// Mitsubishi GX Works2 project: BACK PANEL(TakeOff)(230727)   PLC: Q06UDV

PROGRAM MAIN
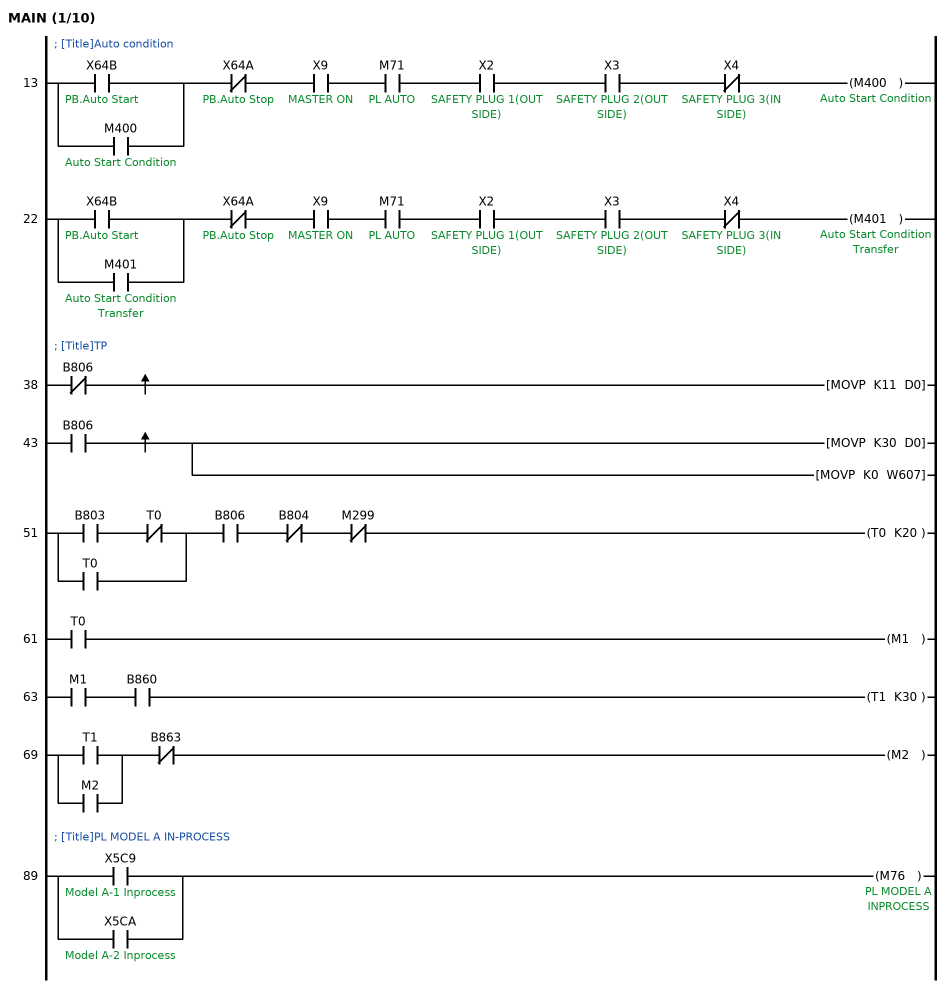
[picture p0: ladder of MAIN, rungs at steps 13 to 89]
; [Title]Auto condition
13    LD      X64B  ; PB.Auto Start
      OR      M400  ; Auto Start Condition
      ANI     X64A  ; PB.Auto Stop
      AND     X9  ; MASTER ON
      AND     M71  ; PL AUTO
      AND     X2  ; SAFETY PLUG 1(OUT SIDE)
      AND     X3  ; SAFETY PLUG 2(OUT SIDE)
      ANI     X4  ; SAFETY PLUG 3(IN SIDE)
      OUT     M400  ; Auto Start Condition
22    LD      X64B  ; PB.Auto Start
      OR      M401  ; Auto Start Condition Transfer
      ANI     X64A  ; PB.Auto Stop
      AND     X9  ; MASTER ON
      AND     M71  ; PL AUTO
      AND     X2  ; SAFETY PLUG 1(OUT SIDE)
      AND     X3  ; SAFETY PLUG 2(OUT SIDE)
      ANI     X4  ; SAFETY PLUG 3(IN SIDE)
      OUT     M401  ; Auto Start Condition Transfer
; [Title]TP
38    LDI     B806
      MEP
      MOVP    K11 D0
43    LD      B806
      MEP
      MOVP    K30 D0
      MOVP    K0 W607
51    LD      B803
      ANI     T0
      OR      T0
      AND     B806
      ANI     B804
      ANI     M299
      OUT     T0 K20
61    LD      T0
      OUT     M1
63    LD      M1
      AND     B860
      OUT     T1 K30
69    LD      T1
      OR      M2
      ANI     B863
      OUT     M2
; [Title]PL MODEL A IN-PROCESS
89    LD      X5C9  ; Model A-1 Inprocess
      OR      X5CA  ; Model A-2 Inprocess
      OUT     M76  ; PL MODEL A INPROCESS
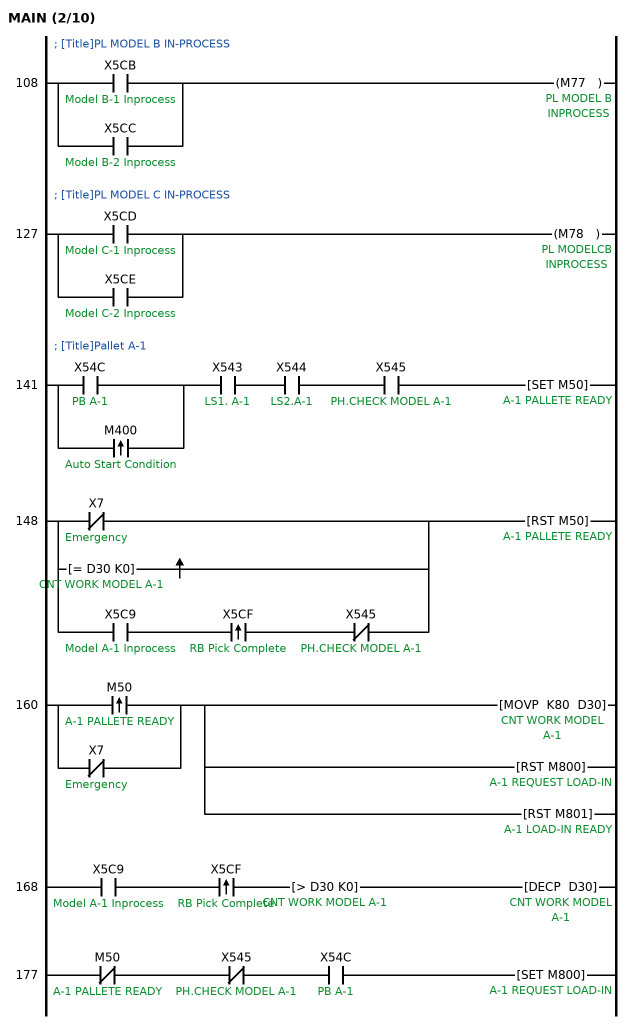
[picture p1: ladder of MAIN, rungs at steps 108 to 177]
; [Title]PL MODEL B IN-PROCESS
108   LD      X5CB  ; Model B-1 Inprocess
      OR      X5CC  ; Model B-2 Inprocess
      OUT     M77  ; PL MODEL B INPROCESS
; [Title]PL MODEL C IN-PROCESS
127   LD      X5CD  ; Model C-1 Inprocess
      OR      X5CE  ; Model C-2 Inprocess
      OUT     M78  ; PL MODELCB INPROCESS
; [Title]Pallet A-1
141   LD      X54C  ; PB A-1
      ORP     M400  ; Auto Start Condition
      AND     X543  ; LS1. A-1
      AND     X544  ; LS2.A-1
      AND     X545  ; PH.CHECK MODEL A-1
      SET     M50  ; A-1 PALLETE READY
148   LDI     X7  ; Emergency
      LD=     D30 K0  ; CNT WORK MODEL A-1
      MEP
      ORB
      LD      X5C9  ; Model A-1 Inprocess
      ANDP    X5CF  ; RB Pick Complete
      ANI     X545  ; PH.CHECK MODEL A-1
      ORB
      RST     M50  ; A-1 PALLETE READY
160   LDP     M50  ; A-1 PALLETE READY
      ORI     X7  ; Emergency
      MOVP    K80 D30
      RST     M800  ; A-1 REQUEST LOAD-IN
      RST     M801  ; A-1 LOAD-IN READY
168   LD      X5C9  ; Model A-1 Inprocess
      ANDP    X5CF  ; RB Pick Complete
      AND>    D30 K0  ; CNT WORK MODEL A-1
      DECP    D30
177   LDI     M50  ; A-1 PALLETE READY
      ANI     X545  ; PH.CHECK MODEL A-1
      AND     X54C  ; PB A-1
      SET     M800  ; A-1 REQUEST LOAD-IN
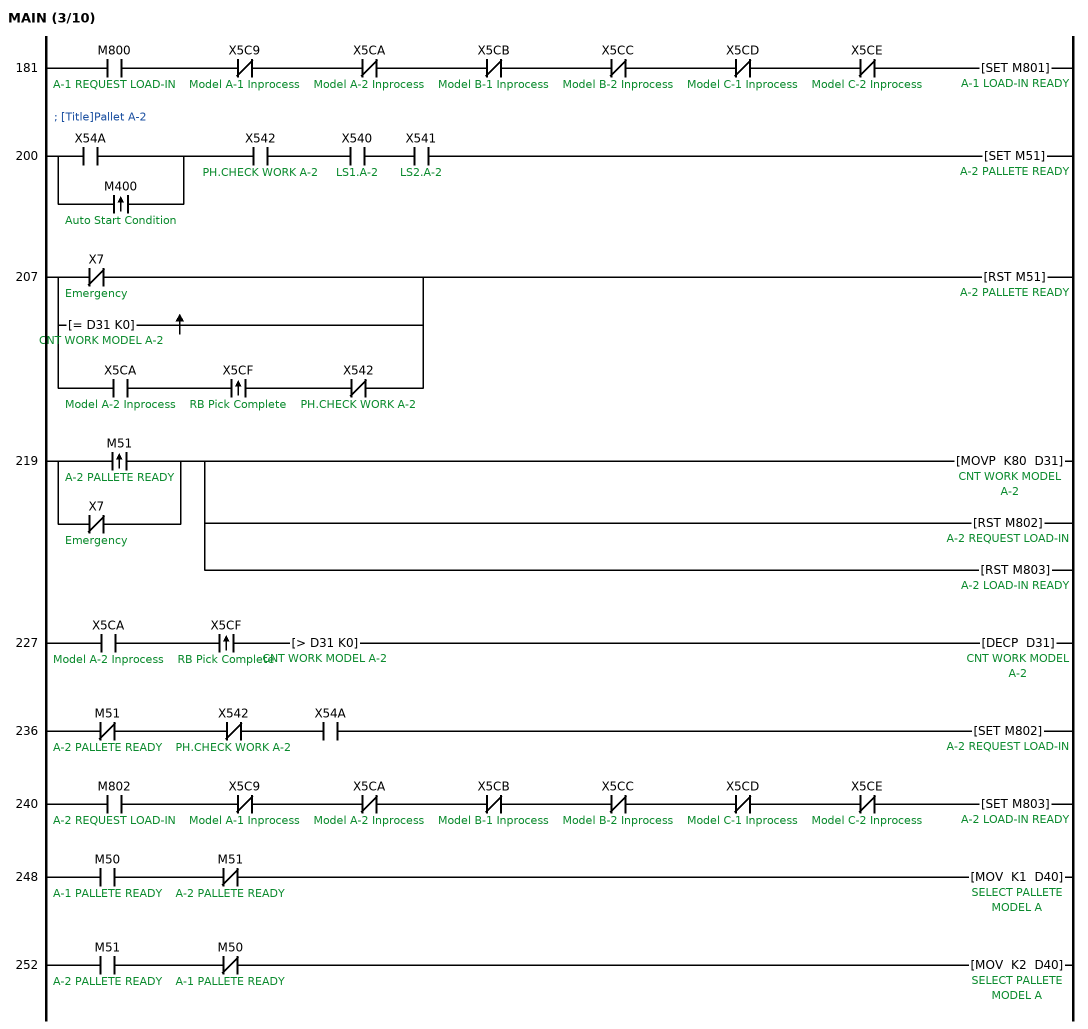
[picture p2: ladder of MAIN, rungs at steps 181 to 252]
181   LD      M800  ; A-1 REQUEST LOAD-IN
      ANI     X5C9  ; Model A-1 Inprocess
      ANI     X5CA  ; Model A-2 Inprocess
      ANI     X5CB  ; Model B-1 Inprocess
      ANI     X5CC  ; Model B-2 Inprocess
      ANI     X5CD  ; Model C-1 Inprocess
      ANI     X5CE  ; Model C-2 Inprocess
      SET     M801  ; A-1 LOAD-IN READY
; [Title]Pallet A-2
200   LD      X54A
      ORP     M400  ; Auto Start Condition
      AND     X542  ; PH.CHECK WORK A-2
      AND     X540  ; LS1.A-2
      AND     X541  ; LS2.A-2
      SET     M51  ; A-2 PALLETE READY
207   LDI     X7  ; Emergency
      LD=     D31 K0  ; CNT WORK MODEL A-2
      MEP
      ORB
      LD      X5CA  ; Model A-2 Inprocess
      ANDP    X5CF  ; RB Pick Complete
      ANI     X542  ; PH.CHECK WORK A-2
      ORB
      RST     M51  ; A-2 PALLETE READY
219   LDP     M51  ; A-2 PALLETE READY
      ORI     X7  ; Emergency
      MOVP    K80 D31
      RST     M802  ; A-2 REQUEST LOAD-IN
      RST     M803  ; A-2 LOAD-IN READY
227   LD      X5CA  ; Model A-2 Inprocess
      ANDP    X5CF  ; RB Pick Complete
      AND>    D31 K0  ; CNT WORK MODEL A-2
      DECP    D31
236   LDI     M51  ; A-2 PALLETE READY
      ANI     X542  ; PH.CHECK WORK A-2
      AND     X54A
      SET     M802  ; A-2 REQUEST LOAD-IN
240   LD      M802  ; A-2 REQUEST LOAD-IN
      ANI     X5C9  ; Model A-1 Inprocess
      ANI     X5CA  ; Model A-2 Inprocess
      ANI     X5CB  ; Model B-1 Inprocess
      ANI     X5CC  ; Model B-2 Inprocess
      ANI     X5CD  ; Model C-1 Inprocess
      ANI     X5CE  ; Model C-2 Inprocess
      SET     M803  ; A-2 LOAD-IN READY
248   LD      M50  ; A-1 PALLETE READY
      ANI     M51  ; A-2 PALLETE READY
      MOV     K1 D40  ; SELECT PALLETE MODEL A
252   LD      M51  ; A-2 PALLETE READY
      ANI     M50  ; A-1 PALLETE READY
      MOV     K2 D40
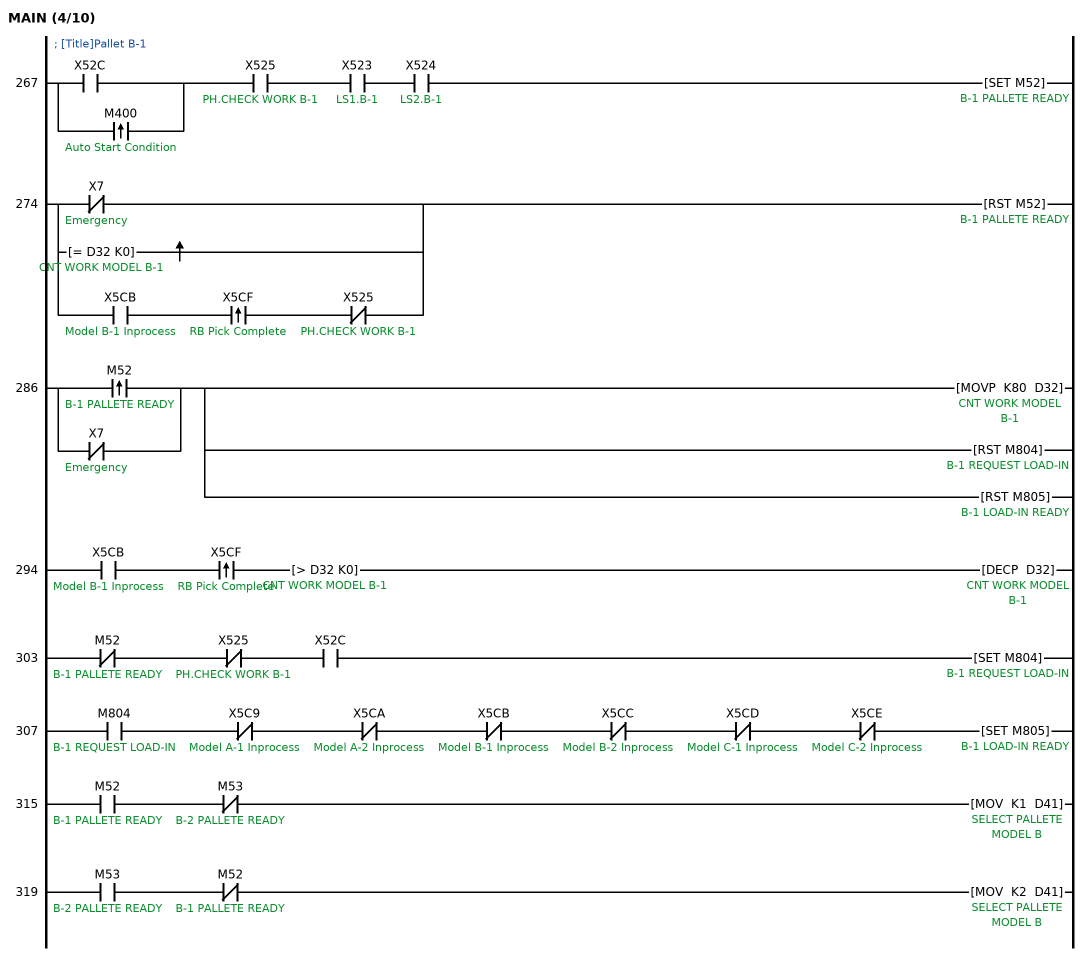
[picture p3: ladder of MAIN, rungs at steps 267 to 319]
; [Title]Pallet B-1
267   LD      X52C
      ORP     M400  ; Auto Start Condition
      AND     X525  ; PH.CHECK WORK B-1
      AND     X523  ; LS1.B-1
      AND     X524  ; LS2.B-1
      SET     M52  ; B-1 PALLETE READY
274   LDI     X7  ; Emergency
      LD=     D32 K0  ; CNT WORK MODEL B-1
      MEP
      ORB
      LD      X5CB  ; Model B-1 Inprocess
      ANDP    X5CF  ; RB Pick Complete
      ANI     X525  ; PH.CHECK WORK B-1
      ORB
      RST     M52  ; B-1 PALLETE READY
286   LDP     M52  ; B-1 PALLETE READY
      ORI     X7  ; Emergency
      MOVP    K80 D32
      RST     M804  ; B-1 REQUEST LOAD-IN
      RST     M805  ; B-1 LOAD-IN READY
294   LD      X5CB  ; Model B-1 Inprocess
      ANDP    X5CF  ; RB Pick Complete
      AND>    D32 K0  ; CNT WORK MODEL B-1
      DECP    D32
303   LDI     M52  ; B-1 PALLETE READY
      ANI     X525  ; PH.CHECK WORK B-1
      AND     X52C
      SET     M804  ; B-1 REQUEST LOAD-IN
307   LD      M804  ; B-1 REQUEST LOAD-IN
      ANI     X5C9  ; Model A-1 Inprocess
      ANI     X5CA  ; Model A-2 Inprocess
      ANI     X5CB  ; Model B-1 Inprocess
      ANI     X5CC  ; Model B-2 Inprocess
      ANI     X5CD  ; Model C-1 Inprocess
      ANI     X5CE  ; Model C-2 Inprocess
      SET     M805  ; B-1 LOAD-IN READY
315   LD      M52  ; B-1 PALLETE READY
      ANI     M53  ; B-2 PALLETE READY
      MOV     K1 D41  ; SELECT PALLETE MODEL B
319   LD      M53  ; B-2 PALLETE READY
      ANI     M52  ; B-1 PALLETE READY
      MOV     K2 D41
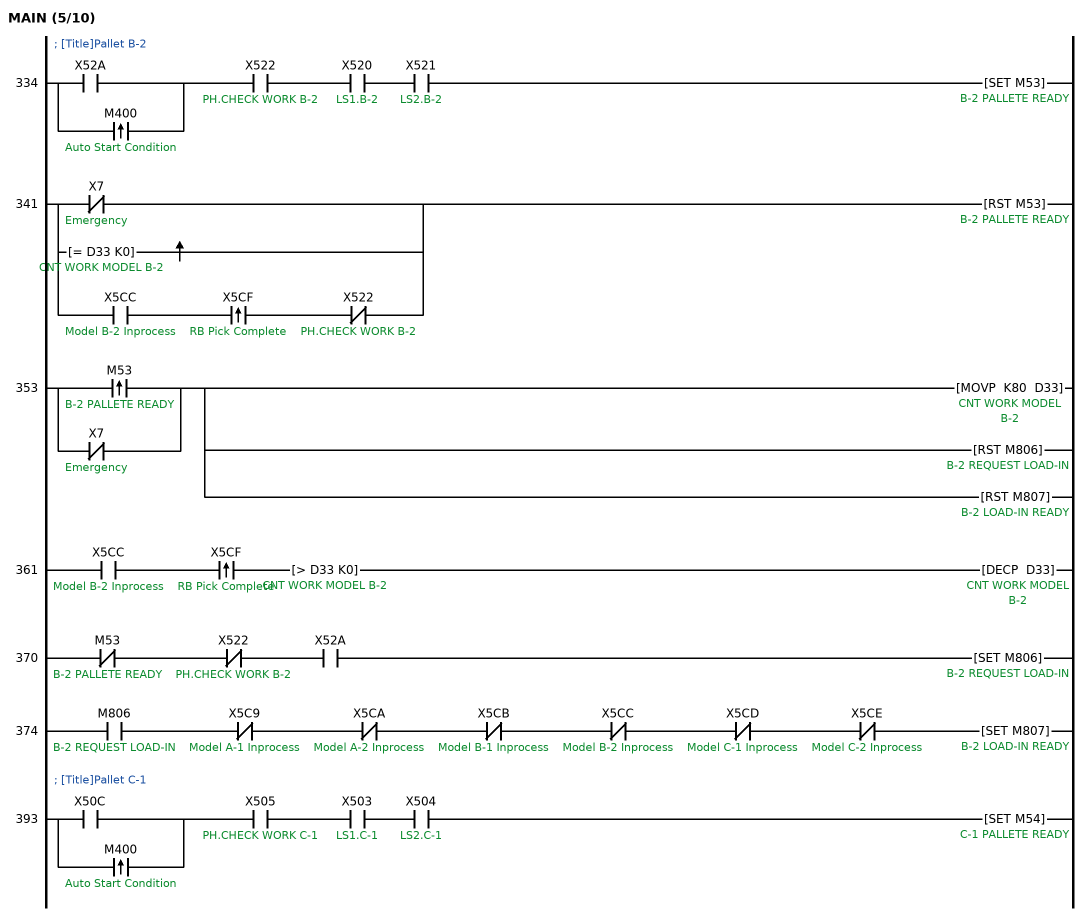
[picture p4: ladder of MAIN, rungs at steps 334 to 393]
; [Title]Pallet B-2
334   LD      X52A
      ORP     M400  ; Auto Start Condition
      AND     X522  ; PH.CHECK WORK B-2
      AND     X520  ; LS1.B-2
      AND     X521  ; LS2.B-2
      SET     M53  ; B-2 PALLETE READY
341   LDI     X7  ; Emergency
      LD=     D33 K0  ; CNT WORK MODEL B-2
      MEP
      ORB
      LD      X5CC  ; Model B-2 Inprocess
      ANDP    X5CF  ; RB Pick Complete
      ANI     X522  ; PH.CHECK WORK B-2
      ORB
      RST     M53  ; B-2 PALLETE READY
353   LDP     M53  ; B-2 PALLETE READY
      ORI     X7  ; Emergency
      MOVP    K80 D33
      RST     M806  ; B-2 REQUEST LOAD-IN
      RST     M807  ; B-2 LOAD-IN READY
361   LD      X5CC  ; Model B-2 Inprocess
      ANDP    X5CF  ; RB Pick Complete
      AND>    D33 K0  ; CNT WORK MODEL B-2
      DECP    D33
370   LDI     M53  ; B-2 PALLETE READY
      ANI     X522  ; PH.CHECK WORK B-2
      AND     X52A
      SET     M806  ; B-2 REQUEST LOAD-IN
374   LD      M806  ; B-2 REQUEST LOAD-IN
      ANI     X5C9  ; Model A-1 Inprocess
      ANI     X5CA  ; Model A-2 Inprocess
      ANI     X5CB  ; Model B-1 Inprocess
      ANI     X5CC  ; Model B-2 Inprocess
      ANI     X5CD  ; Model C-1 Inprocess
      ANI     X5CE  ; Model C-2 Inprocess
      SET     M807  ; B-2 LOAD-IN READY
; [Title]Pallet C-1
393   LD      X50C
      ORP     M400  ; Auto Start Condition
      AND     X505  ; PH.CHECK WORK C-1
      AND     X503  ; LS1.C-1
      AND     X504  ; LS2.C-1
      SET     M54  ; C-1 PALLETE READY
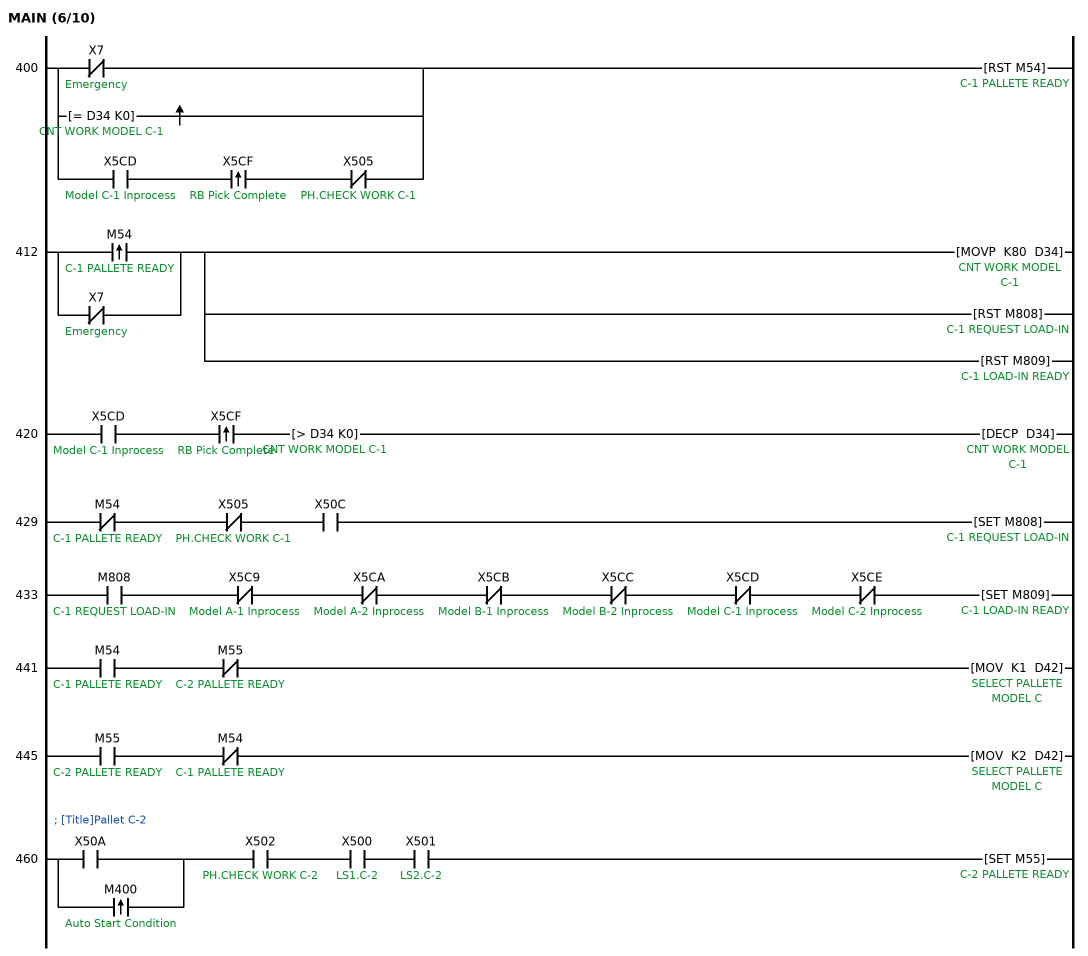
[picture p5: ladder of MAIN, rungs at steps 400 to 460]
400   LDI     X7  ; Emergency
      LD=     D34 K0  ; CNT WORK MODEL C-1
      MEP
      ORB
      LD      X5CD  ; Model C-1 Inprocess
      ANDP    X5CF  ; RB Pick Complete
      ANI     X505  ; PH.CHECK WORK C-1
      ORB
      RST     M54  ; C-1 PALLETE READY
412   LDP     M54  ; C-1 PALLETE READY
      ORI     X7  ; Emergency
      MOVP    K80 D34
      RST     M808  ; C-1 REQUEST LOAD-IN
      RST     M809  ; C-1 LOAD-IN READY
420   LD      X5CD  ; Model C-1 Inprocess
      ANDP    X5CF  ; RB Pick Complete
      AND>    D34 K0  ; CNT WORK MODEL C-1
      DECP    D34
429   LDI     M54  ; C-1 PALLETE READY
      ANI     X505  ; PH.CHECK WORK C-1
      AND     X50C
      SET     M808  ; C-1 REQUEST LOAD-IN
433   LD      M808  ; C-1 REQUEST LOAD-IN
      ANI     X5C9  ; Model A-1 Inprocess
      ANI     X5CA  ; Model A-2 Inprocess
      ANI     X5CB  ; Model B-1 Inprocess
      ANI     X5CC  ; Model B-2 Inprocess
      ANI     X5CD  ; Model C-1 Inprocess
      ANI     X5CE  ; Model C-2 Inprocess
      SET     M809  ; C-1 LOAD-IN READY
441   LD      M54  ; C-1 PALLETE READY
      ANI     M55  ; C-2 PALLETE READY
      MOV     K1 D42  ; SELECT PALLETE MODEL C
445   LD      M55  ; C-2 PALLETE READY
      ANI     M54  ; C-1 PALLETE READY
      MOV     K2 D42
; [Title]Pallet C-2
460   LD      X50A
      ORP     M400  ; Auto Start Condition
      AND     X502  ; PH.CHECK WORK C-2
      AND     X500  ; LS1.C-2
      AND     X501  ; LS2.C-2
      SET     M55  ; C-2 PALLETE READY
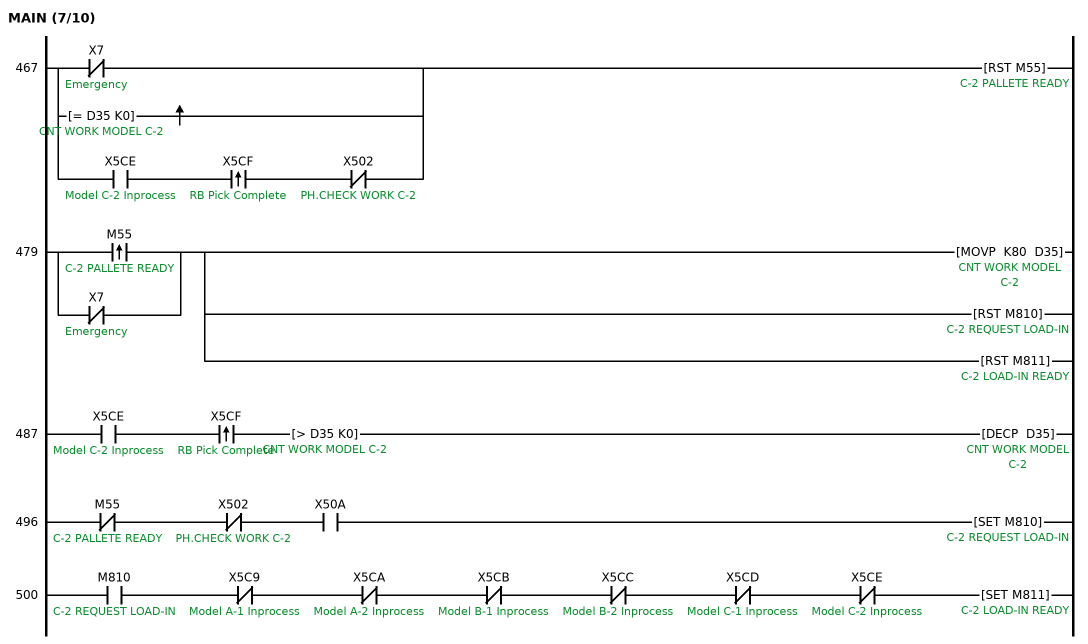
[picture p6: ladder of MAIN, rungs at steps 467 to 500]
467   LDI     X7  ; Emergency
      LD=     D35 K0  ; CNT WORK MODEL C-2
      MEP
      ORB
      LD      X5CE  ; Model C-2 Inprocess
      ANDP    X5CF  ; RB Pick Complete
      ANI     X502  ; PH.CHECK WORK C-2
      ORB
      RST     M55  ; C-2 PALLETE READY
479   LDP     M55  ; C-2 PALLETE READY
      ORI     X7  ; Emergency
      MOVP    K80 D35
      RST     M810  ; C-2 REQUEST LOAD-IN
      RST     M811  ; C-2 LOAD-IN READY
487   LD      X5CE  ; Model C-2 Inprocess
      ANDP    X5CF  ; RB Pick Complete
      AND>    D35 K0  ; CNT WORK MODEL C-2
      DECP    D35
496   LDI     M55  ; C-2 PALLETE READY
      ANI     X502  ; PH.CHECK WORK C-2
      AND     X50A
      SET     M810  ; C-2 REQUEST LOAD-IN
500   LD      M810  ; C-2 REQUEST LOAD-IN
      ANI     X5C9  ; Model A-1 Inprocess
      ANI     X5CA  ; Model A-2 Inprocess
      ANI     X5CB  ; Model B-1 Inprocess
      ANI     X5CC  ; Model B-2 Inprocess
      ANI     X5CD  ; Model C-1 Inprocess
      ANI     X5CE  ; Model C-2 Inprocess
      SET     M811  ; C-2 LOAD-IN READY
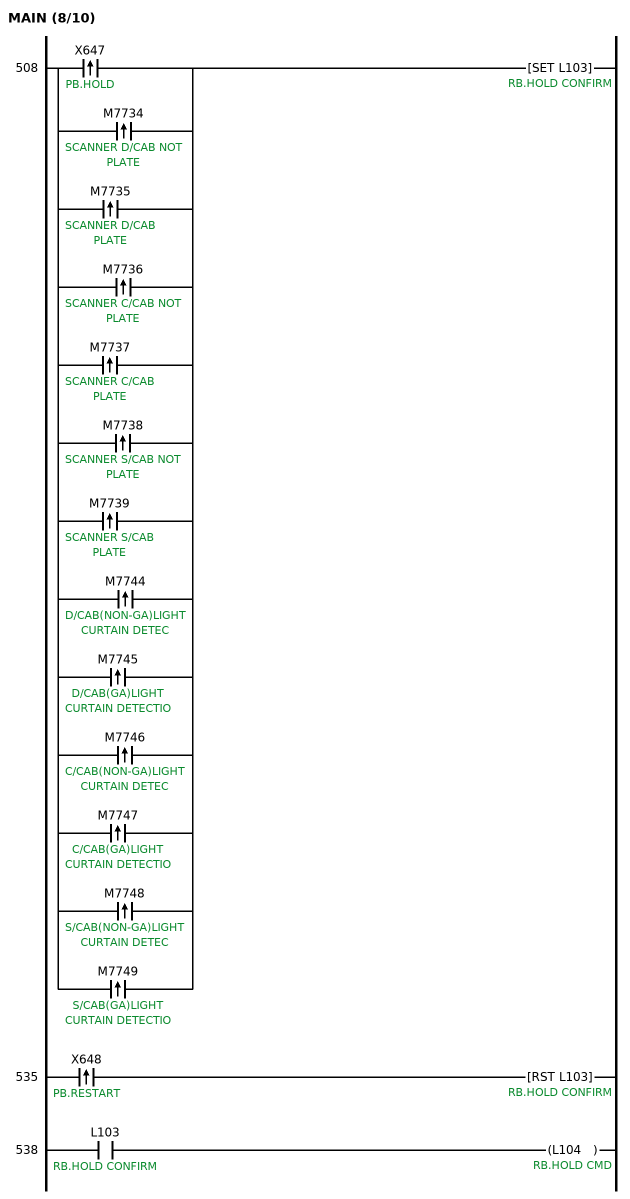
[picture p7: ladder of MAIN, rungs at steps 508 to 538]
508   LDP     X647  ; PB.HOLD
      ORP     M7734  ; SCANNER D/CAB NOT PLATE
      ORP     M7735  ; SCANNER D/CAB PLATE
      ORP     M7736  ; SCANNER C/CAB NOT PLATE
      ORP     M7737  ; SCANNER C/CAB  PLATE
      ORP     M7738  ; SCANNER S/CAB NOT PLATE
      ORP     M7739  ; SCANNER S/CAB  PLATE
      ORP     M7744  ; D/CAB(NON-GA)LIGHT CURTAIN DETEC
      ORP     M7745  ; D/CAB(GA)LIGHT  CURTAIN DETECTIO
      ORP     M7746  ; C/CAB(NON-GA)LIGHT CURTAIN DETEC
      ORP     M7747  ; C/CAB(GA)LIGHT  CURTAIN DETECTIO
      ORP     M7748  ; S/CAB(NON-GA)LIGHT CURTAIN DETEC
      ORP     M7749  ; S/CAB(GA)LIGHT  CURTAIN DETECTIO
      SET     L103  ; RB.HOLD CONFIRM
535   LDP     X648  ; PB.RESTART
      RST     L103  ; RB.HOLD CONFIRM
538   LD      L103  ; RB.HOLD CONFIRM
      OUT     L104  ; RB.HOLD CMD
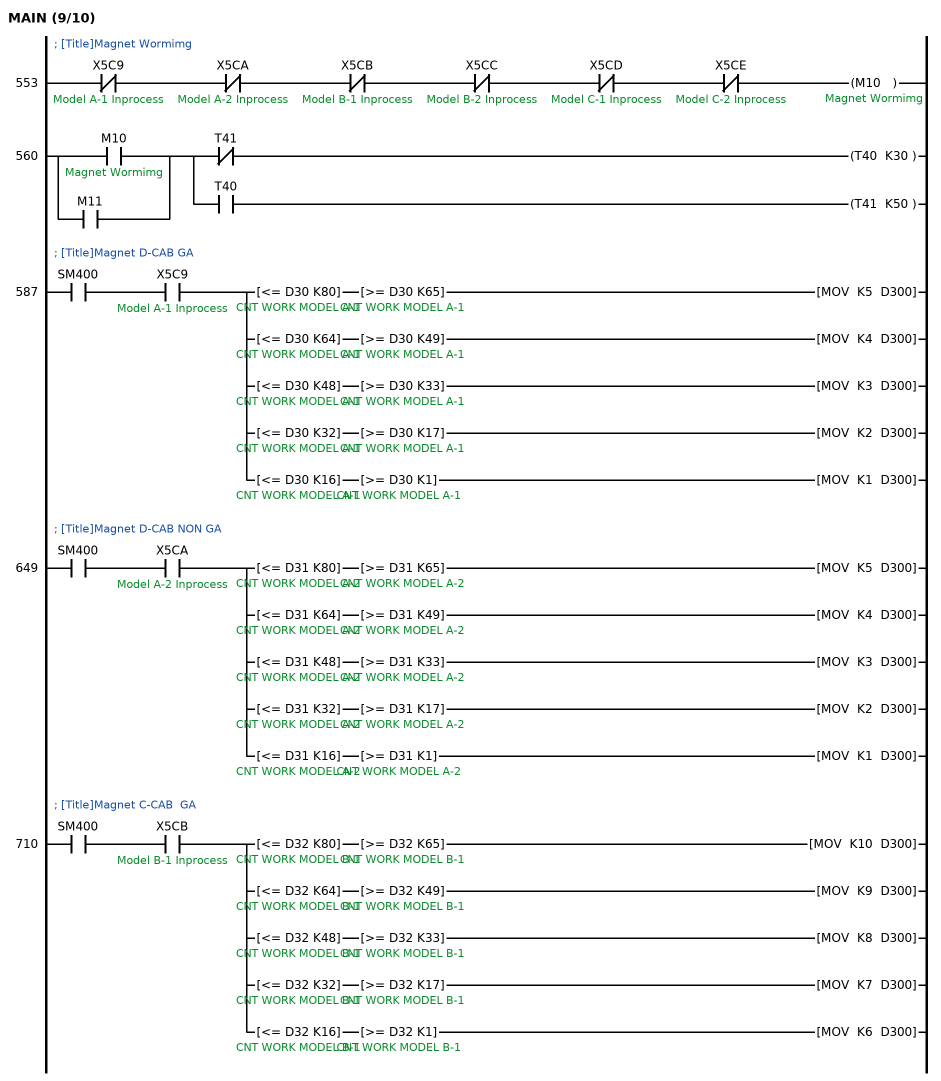
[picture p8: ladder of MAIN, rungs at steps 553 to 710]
; [Title]Magnet Wormimg
553   LDI     X5C9  ; Model A-1 Inprocess
      ANI     X5CA  ; Model A-2 Inprocess
      ANI     X5CB  ; Model B-1 Inprocess
      ANI     X5CC  ; Model B-2 Inprocess
      ANI     X5CD  ; Model C-1 Inprocess
      ANI     X5CE  ; Model C-2 Inprocess
      OUT     M10  ; Magnet Wormimg
560   LD      M10  ; Magnet Wormimg
      OR      M11
      MPS
      ANI     T41
      OUT     T40 K30
      MPP
      AND     T40
      OUT     T41 K50
; [Title]Magnet D-CAB GA
587   LD      SM400
      AND     X5C9  ; Model A-1 Inprocess
      MPS
      AND<=   D30 K80  ; CNT WORK MODEL A-1
      AND>=   D30 K65  ; CNT WORK MODEL A-1
      MOV     K5 D300
      MRD
      AND<=   D30 K64  ; CNT WORK MODEL A-1
      AND>=   D30 K49  ; CNT WORK MODEL A-1
      MOV     K4 D300
      MRD
      AND<=   D30 K48  ; CNT WORK MODEL A-1
      AND>=   D30 K33  ; CNT WORK MODEL A-1
      MOV     K3 D300
      MRD
      AND<=   D30 K32  ; CNT WORK MODEL A-1
      AND>=   D30 K17  ; CNT WORK MODEL A-1
      MOV     K2 D300
      MPP
      AND<=   D30 K16  ; CNT WORK MODEL A-1
      AND>=   D30 K1  ; CNT WORK MODEL A-1
      MOV     K1 D300
; [Title]Magnet D-CAB NON GA
649   LD      SM400
      AND     X5CA  ; Model A-2 Inprocess
      MPS
      AND<=   D31 K80  ; CNT WORK MODEL A-2
      AND>=   D31 K65  ; CNT WORK MODEL A-2
      MOV     K5 D300
      MRD
      AND<=   D31 K64  ; CNT WORK MODEL A-2
      AND>=   D31 K49  ; CNT WORK MODEL A-2
      MOV     K4 D300
      MRD
      AND<=   D31 K48  ; CNT WORK MODEL A-2
      AND>=   D31 K33  ; CNT WORK MODEL A-2
      MOV     K3 D300
      MRD
      AND<=   D31 K32  ; CNT WORK MODEL A-2
      AND>=   D31 K17  ; CNT WORK MODEL A-2
      MOV     K2 D300
      MPP
      AND<=   D31 K16  ; CNT WORK MODEL A-2
      AND>=   D31 K1  ; CNT WORK MODEL A-2
      MOV     K1 D300
; [Title]Magnet C-CAB  GA
710   LD      SM400
      AND     X5CB  ; Model B-1 Inprocess
      MPS
      AND<=   D32 K80  ; CNT WORK MODEL B-1
      AND>=   D32 K65  ; CNT WORK MODEL B-1
      MOV     K10 D300
      MRD
      AND<=   D32 K64  ; CNT WORK MODEL B-1
      AND>=   D32 K49  ; CNT WORK MODEL B-1
      MOV     K9 D300
      MRD
      AND<=   D32 K48  ; CNT WORK MODEL B-1
      AND>=   D32 K33  ; CNT WORK MODEL B-1
      MOV     K8 D300
      MRD
      AND<=   D32 K32  ; CNT WORK MODEL B-1
      AND>=   D32 K17  ; CNT WORK MODEL B-1
      MOV     K7 D300
      MPP
      AND<=   D32 K16  ; CNT WORK MODEL B-1
      AND>=   D32 K1  ; CNT WORK MODEL B-1
      MOV     K6 D300
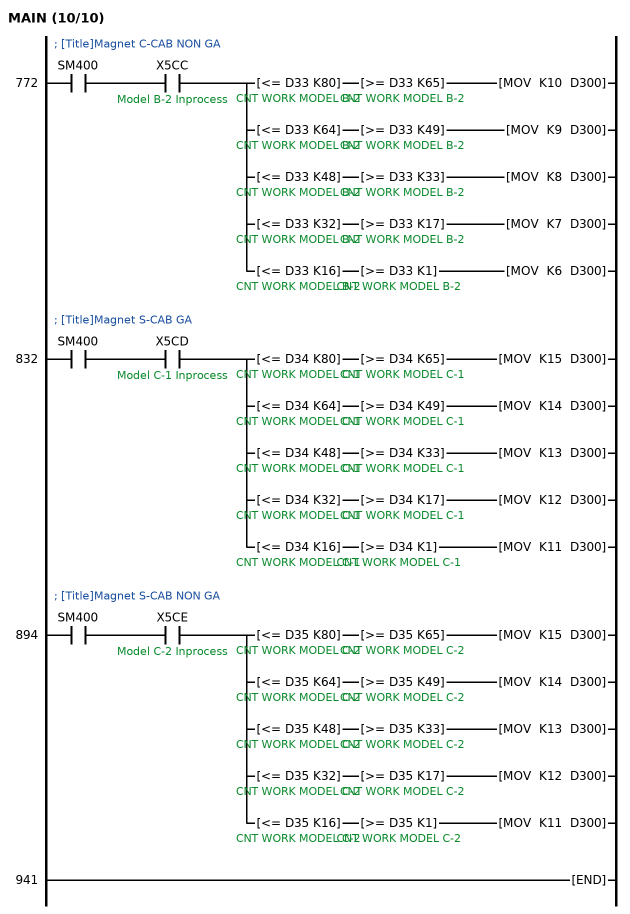
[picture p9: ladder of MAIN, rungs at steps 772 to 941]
; [Title]Magnet C-CAB NON GA
772   LD      SM400
      AND     X5CC  ; Model B-2 Inprocess
      MPS
      AND<=   D33 K80  ; CNT WORK MODEL B-2
      AND>=   D33 K65  ; CNT WORK MODEL B-2
      MOV     K10 D300
      MRD
      AND<=   D33 K64  ; CNT WORK MODEL B-2
      AND>=   D33 K49  ; CNT WORK MODEL B-2
      MOV     K9 D300
      MRD
      AND<=   D33 K48  ; CNT WORK MODEL B-2
      AND>=   D33 K33  ; CNT WORK MODEL B-2
      MOV     K8 D300
      MRD
      AND<=   D33 K32  ; CNT WORK MODEL B-2
      AND>=   D33 K17  ; CNT WORK MODEL B-2
      MOV     K7 D300
      MPP
      AND<=   D33 K16  ; CNT WORK MODEL B-2
      AND>=   D33 K1  ; CNT WORK MODEL B-2
      MOV     K6 D300
; [Title]Magnet S-CAB GA
832   LD      SM400
      AND     X5CD  ; Model C-1 Inprocess
      MPS
      AND<=   D34 K80  ; CNT WORK MODEL C-1
      AND>=   D34 K65  ; CNT WORK MODEL C-1
      MOV     K15 D300
      MRD
      AND<=   D34 K64  ; CNT WORK MODEL C-1
      AND>=   D34 K49  ; CNT WORK MODEL C-1
      MOV     K14 D300
      MRD
      AND<=   D34 K48  ; CNT WORK MODEL C-1
      AND>=   D34 K33  ; CNT WORK MODEL C-1
      MOV     K13 D300
      MRD
      AND<=   D34 K32  ; CNT WORK MODEL C-1
      AND>=   D34 K17  ; CNT WORK MODEL C-1
      MOV     K12 D300
      MPP
      AND<=   D34 K16  ; CNT WORK MODEL C-1
      AND>=   D34 K1  ; CNT WORK MODEL C-1
      MOV     K11 D300
; [Title]Magnet S-CAB NON GA
894   LD      SM400
      AND     X5CE  ; Model C-2 Inprocess
      MPS
      AND<=   D35 K80  ; CNT WORK MODEL C-2
      AND>=   D35 K65  ; CNT WORK MODEL C-2
      MOV     K15 D300
      MRD
      AND<=   D35 K64  ; CNT WORK MODEL C-2
      AND>=   D35 K49  ; CNT WORK MODEL C-2
      MOV     K14 D300
      MRD
      AND<=   D35 K48  ; CNT WORK MODEL C-2
      AND>=   D35 K33  ; CNT WORK MODEL C-2
      MOV     K13 D300
      MRD
      AND<=   D35 K32  ; CNT WORK MODEL C-2
      AND>=   D35 K17  ; CNT WORK MODEL C-2
      MOV     K12 D300
      MPP
      AND<=   D35 K16  ; CNT WORK MODEL C-2
      AND>=   D35 K1  ; CNT WORK MODEL C-2
      MOV     K11 D300
941   END
END_PROGRAM

PROGRAM MANUAL
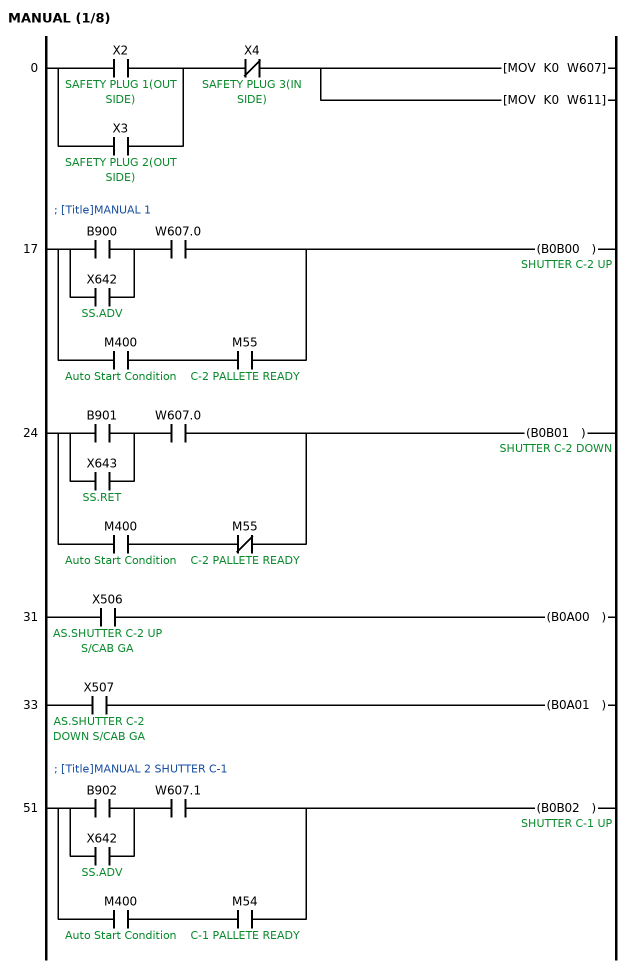
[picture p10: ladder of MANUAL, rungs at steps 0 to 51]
0     LD      X2  ; SAFETY PLUG 1(OUT SIDE)
      OR      X3  ; SAFETY PLUG 2(OUT SIDE)
      ANI     X4  ; SAFETY PLUG 3(IN SIDE)
      MOV     K0 W607
      MOV     K0 W611
; [Title]MANUAL 1
17    LD      B900
      OR      X642  ; SS.ADV
      AND     W607.0
      LD      M400  ; Auto Start Condition
      AND     M55  ; C-2 PALLETE READY
      ORB
      OUT     B0B00  ; SHUTTER C-2 UP
24    LD      B901
      OR      X643  ; SS.RET
      AND     W607.0
      LD      M400  ; Auto Start Condition
      ANI     M55  ; C-2 PALLETE READY
      ORB
      OUT     B0B01  ; SHUTTER C-2 DOWN
31    LD      X506  ; AS.SHUTTER C-2 UP S/CAB GA
      OUT     B0A00
33    LD      X507  ; AS.SHUTTER C-2 DOWN S/CAB GA
      OUT     B0A01
; [Title]MANUAL 2 SHUTTER C-1
51    LD      B902
      OR      X642  ; SS.ADV
      AND     W607.1
      LD      M400  ; Auto Start Condition
      AND     M54  ; C-1 PALLETE READY
      ORB
      OUT     B0B02  ; SHUTTER C-1 UP
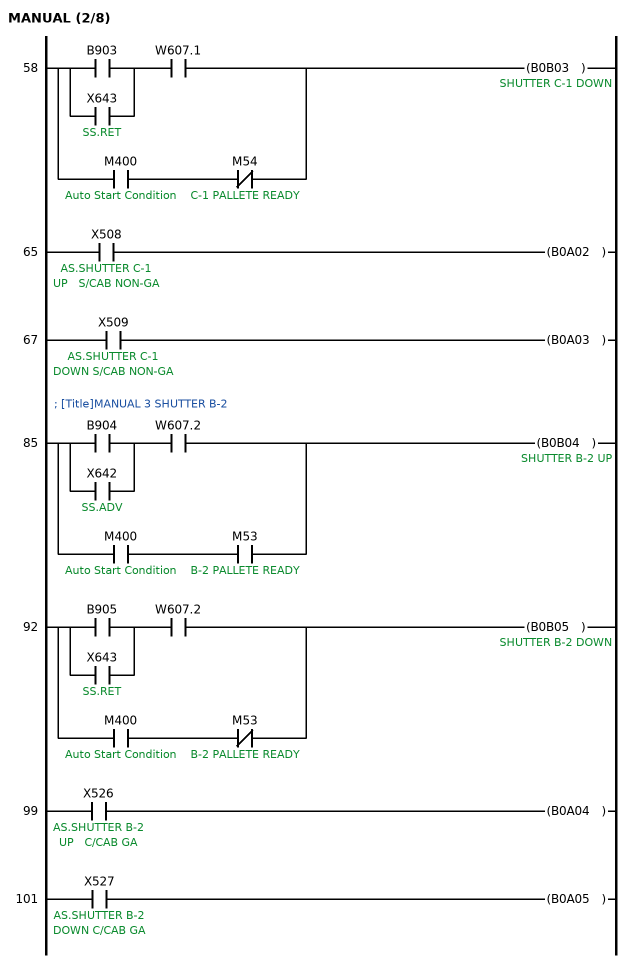
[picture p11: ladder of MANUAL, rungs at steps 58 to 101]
58    LD      B903
      OR      X643  ; SS.RET
      AND     W607.1
      LD      M400  ; Auto Start Condition
      ANI     M54  ; C-1 PALLETE READY
      ORB
      OUT     B0B03  ; SHUTTER C-1 DOWN
65    LD      X508  ; AS.SHUTTER C-1 UP　S/CAB NON-GA
      OUT     B0A02
67    LD      X509  ; AS.SHUTTER C-1 DOWN S/CAB NON-GA
      OUT     B0A03
; [Title]MANUAL 3 SHUTTER B-2
85    LD      B904
      OR      X642  ; SS.ADV
      AND     W607.2
      LD      M400  ; Auto Start Condition
      AND     M53  ; B-2 PALLETE READY
      ORB
      OUT     B0B04  ; SHUTTER B-2 UP
92    LD      B905
      OR      X643  ; SS.RET
      AND     W607.2
      LD      M400  ; Auto Start Condition
      ANI     M53  ; B-2 PALLETE READY
      ORB
      OUT     B0B05  ; SHUTTER B-2 DOWN
99    LD      X526  ; AS.SHUTTER B-2 UP　C/CAB GA
      OUT     B0A04
101   LD      X527  ; AS.SHUTTER B-2 DOWN C/CAB GA
      OUT     B0A05
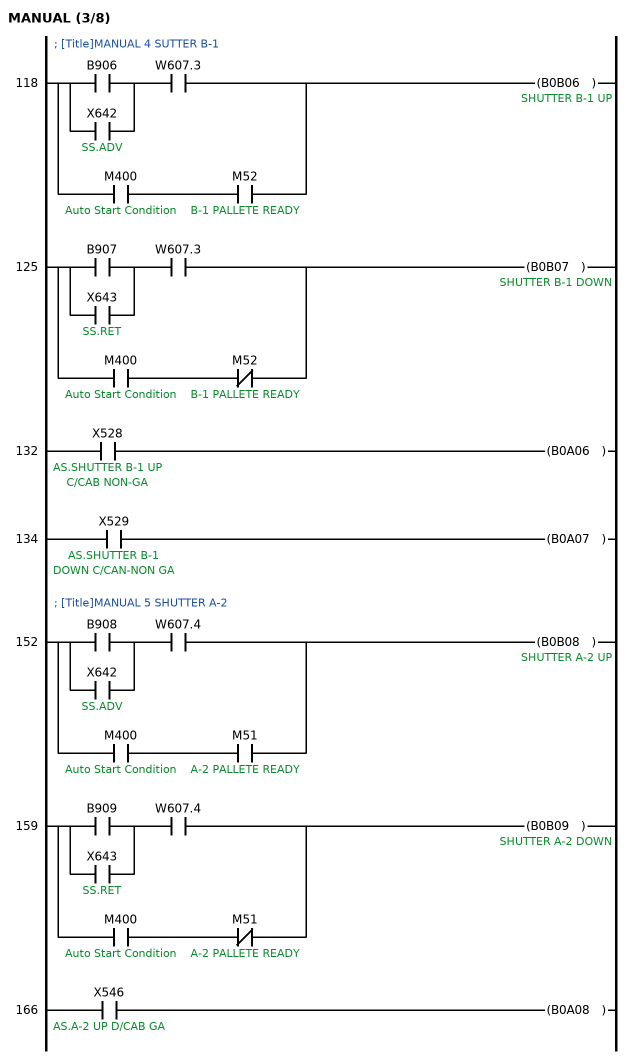
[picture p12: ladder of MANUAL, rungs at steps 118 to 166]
; [Title]MANUAL 4 SUTTER B-1
118   LD      B906
      OR      X642  ; SS.ADV
      AND     W607.3
      LD      M400  ; Auto Start Condition
      AND     M52  ; B-1 PALLETE READY
      ORB
      OUT     B0B06  ; SHUTTER B-1 UP
125   LD      B907
      OR      X643  ; SS.RET
      AND     W607.3
      LD      M400  ; Auto Start Condition
      ANI     M52  ; B-1 PALLETE READY
      ORB
      OUT     B0B07  ; SHUTTER B-1 DOWN
132   LD      X528  ; AS.SHUTTER B-1 UP C/CAB NON-GA
      OUT     B0A06
134   LD      X529  ; AS.SHUTTER B-1 DOWN C/CAN-NON GA
      OUT     B0A07
; [Title]MANUAL 5 SHUTTER A-2
152   LD      B908
      OR      X642  ; SS.ADV
      AND     W607.4
      LD      M400  ; Auto Start Condition
      AND     M51  ; A-2 PALLETE READY
      ORB
      OUT     B0B08  ; SHUTTER A-2 UP
159   LD      B909
      OR      X643  ; SS.RET
      AND     W607.4
      LD      M400  ; Auto Start Condition
      ANI     M51  ; A-2 PALLETE READY
      ORB
      OUT     B0B09  ; SHUTTER A-2 DOWN
166   LD      X546  ; AS.A-2 UP D/CAB GA
      OUT     B0A08
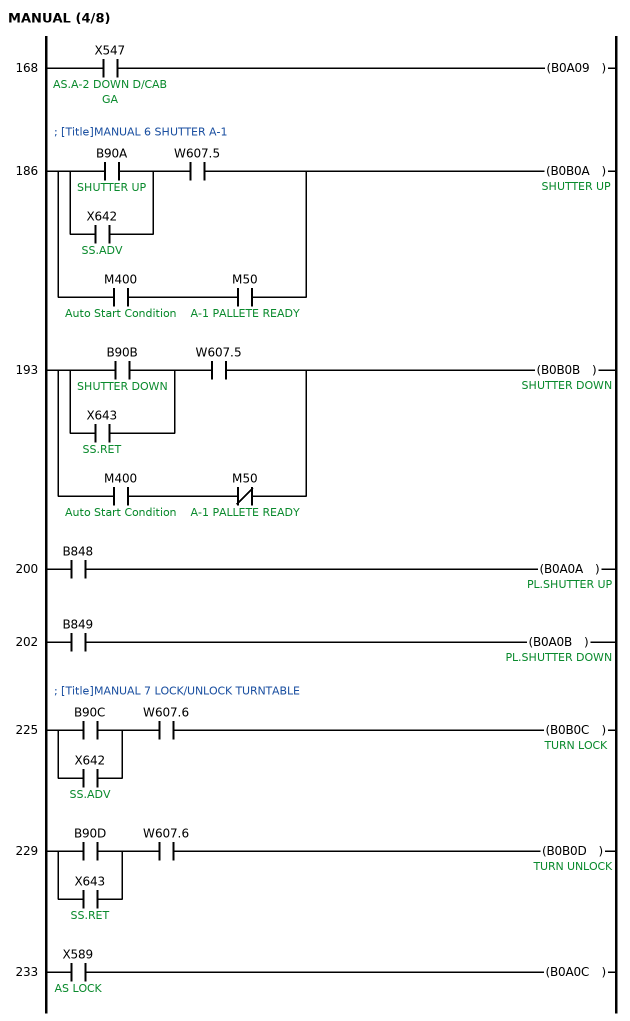
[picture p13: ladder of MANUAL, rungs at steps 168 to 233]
168   LD      X547  ; AS.A-2 DOWN D/CAB GA
      OUT     B0A09
; [Title]MANUAL 6 SHUTTER A-1
186   LD      B90A  ; SHUTTER UP
      OR      X642  ; SS.ADV
      AND     W607.5
      LD      M400  ; Auto Start Condition
      AND     M50  ; A-1 PALLETE READY
      ORB
      OUT     B0B0A  ; SHUTTER UP
193   LD      B90B  ; SHUTTER DOWN
      OR      X643  ; SS.RET
      AND     W607.5
      LD      M400  ; Auto Start Condition
      ANI     M50  ; A-1 PALLETE READY
      ORB
      OUT     B0B0B  ; SHUTTER DOWN
200   LD      B848
      OUT     B0A0A  ; PL.SHUTTER UP
202   LD      B849
      OUT     B0A0B  ; PL.SHUTTER DOWN
; [Title]MANUAL 7 LOCK/UNLOCK TURNTABLE
225   LD      B90C
      OR      X642  ; SS.ADV
      AND     W607.6
      OUT     B0B0C  ; TURN LOCK
229   LD      B90D
      OR      X643  ; SS.RET
      AND     W607.6
      OUT     B0B0D  ; TURN UNLOCK
233   LD      X589  ; AS LOCK
      OUT     B0A0C
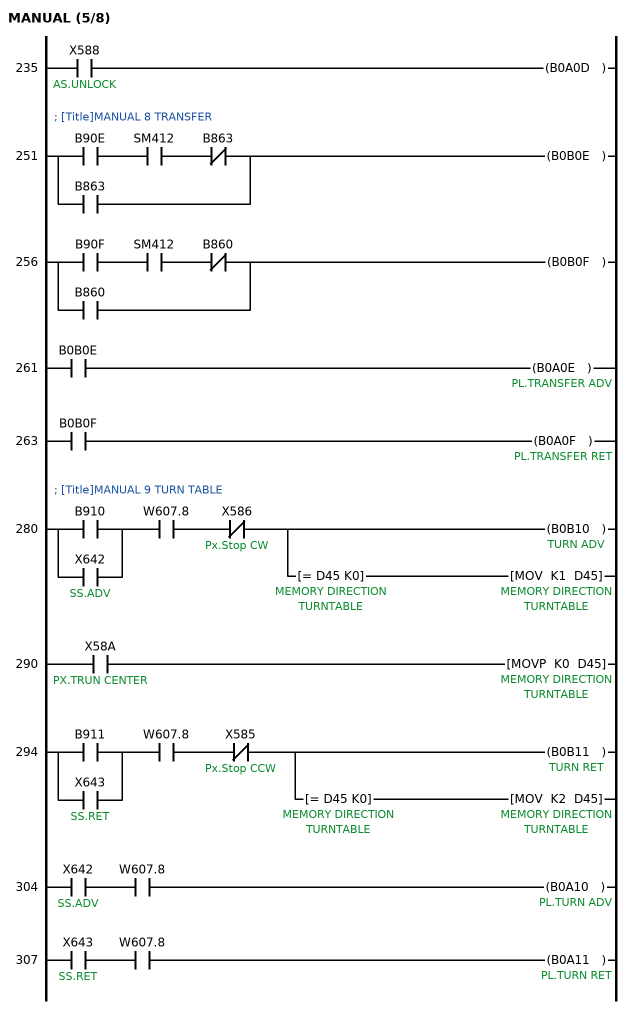
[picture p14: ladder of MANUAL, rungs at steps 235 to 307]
235   LD      X588  ; AS.UNLOCK
      OUT     B0A0D
; [Title]MANUAL 8 TRANSFER
251   LD      B90E
      AND     SM412
      ANI     B863
      OR      B863
      OUT     B0B0E
256   LD      B90F
      AND     SM412
      ANI     B860
      OR      B860
      OUT     B0B0F
261   LD      B0B0E
      OUT     B0A0E  ; PL.TRANSFER ADV
263   LD      B0B0F
      OUT     B0A0F  ; PL.TRANSFER RET
; [Title]MANUAL 9 TURN TABLE
280   LD      B910
      OR      X642  ; SS.ADV
      AND     W607.8
      ANI     X586  ; Px.Stop CW
      OUT     B0B10  ; TURN ADV
      AND=    D45 K0  ; MEMORY DIRECTION TURNTABLE
      MOV     K1 D45
290   LD      X58A  ; PX.TRUN CENTER
      MOVP    K0 D45
294   LD      B911
      OR      X643  ; SS.RET
      AND     W607.8
      ANI     X585  ; Px.Stop CCW
      OUT     B0B11  ; TURN RET
      AND=    D45 K0  ; MEMORY DIRECTION TURNTABLE
      MOV     K2 D45
304   LD      X642  ; SS.ADV
      AND     W607.8
      OUT     B0A10  ; PL.TURN ADV
307   LD      X643  ; SS.RET
      AND     W607.8
      OUT     B0A11  ; PL.TURN RET
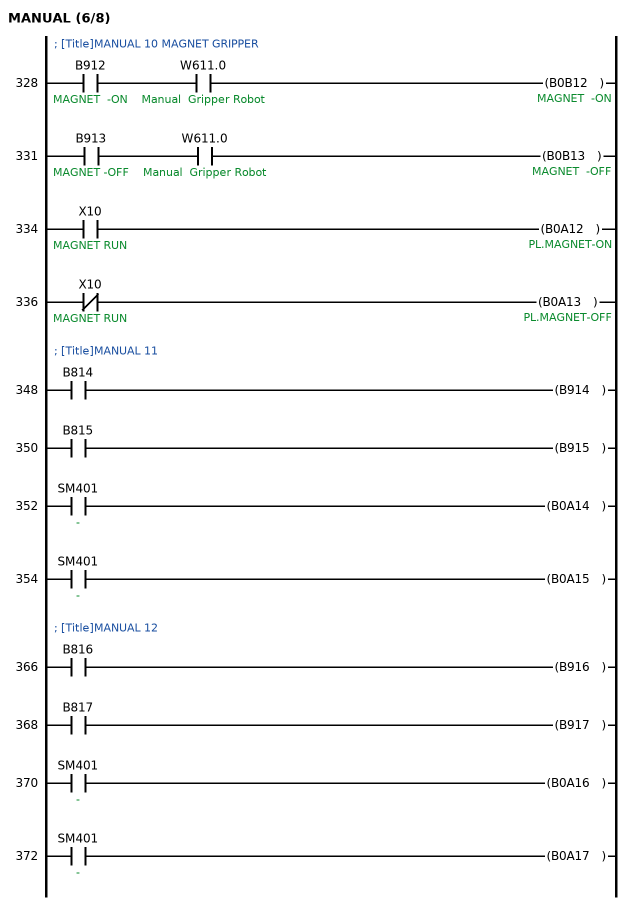
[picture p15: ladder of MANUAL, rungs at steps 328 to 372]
; [Title]MANUAL 10 MAGNET GRIPPER
328   LD      B912  ; MAGNET  -ON
      AND     W611.0  ; Manual  Gripper Robot
      OUT     B0B12  ; MAGNET  -ON
331   LD      B913  ; MAGNET -OFF
      AND     W611.0  ; Manual  Gripper Robot
      OUT     B0B13  ; MAGNET  -OFF
334   LD      X10  ; MAGNET RUN
      OUT     B0A12  ; PL.MAGNET-ON
336   LDI     X10  ; MAGNET RUN
      OUT     B0A13  ; PL.MAGNET-OFF
; [Title]MANUAL 11
348   LD      B814
      OUT     B914
350   LD      B815
      OUT     B915
352   LD      SM401  ; -
      OUT     B0A14
354   LD      SM401  ; -
      OUT     B0A15
; [Title]MANUAL 12
366   LD      B816
      OUT     B916
368   LD      B817
      OUT     B917
370   LD      SM401  ; -
      OUT     B0A16
372   LD      SM401  ; -
      OUT     B0A17
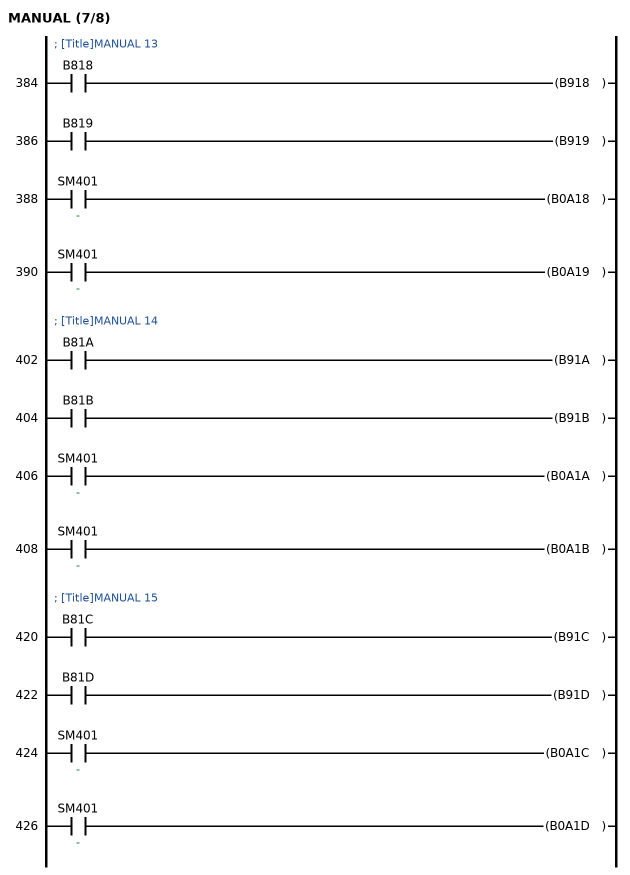
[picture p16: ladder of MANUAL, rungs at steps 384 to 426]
; [Title]MANUAL 13
384   LD      B818
      OUT     B918
386   LD      B819
      OUT     B919
388   LD      SM401  ; -
      OUT     B0A18
390   LD      SM401  ; -
      OUT     B0A19
; [Title]MANUAL 14
402   LD      B81A
      OUT     B91A
404   LD      B81B
      OUT     B91B
406   LD      SM401  ; -
      OUT     B0A1A
408   LD      SM401  ; -
      OUT     B0A1B
; [Title]MANUAL 15
420   LD      B81C
      OUT     B91C
422   LD      B81D
      OUT     B91D
424   LD      SM401  ; -
      OUT     B0A1C
426   LD      SM401  ; -
      OUT     B0A1D
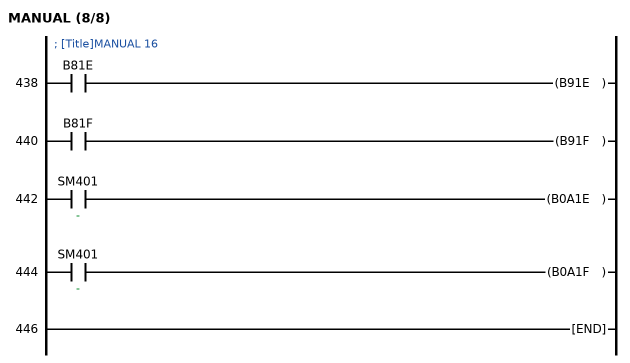
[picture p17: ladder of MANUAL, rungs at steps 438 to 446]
; [Title]MANUAL 16
438   LD      B81E
      OUT     B91E
440   LD      B81F
      OUT     B91F
442   LD      SM401  ; -
      OUT     B0A1E
444   LD      SM401  ; -
      OUT     B0A1F
446   END
END_PROGRAM

PROGRAM INPUT
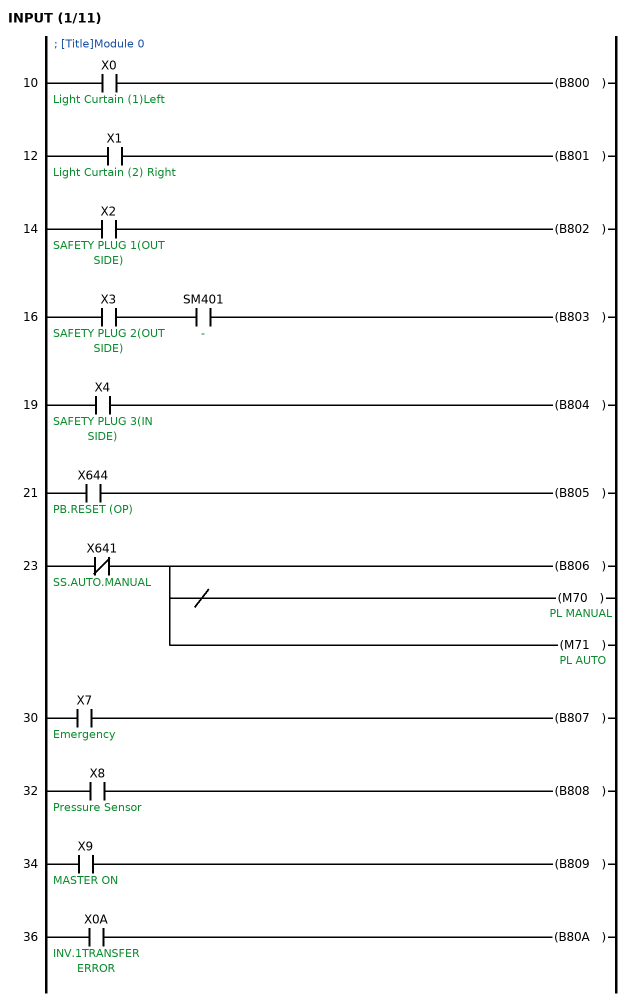
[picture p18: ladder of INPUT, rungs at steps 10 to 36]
; [Title]Module 0
10    LD      X0  ; Light Curtain (1)Left
      OUT     B800
12    LD      X1  ; Light Curtain (2) Right
      OUT     B801
14    LD      X2  ; SAFETY PLUG 1(OUT SIDE)
      OUT     B802
16    LD      X3  ; SAFETY PLUG 2(OUT SIDE)
      AND     SM401  ; -
      OUT     B803
19    LD      X4  ; SAFETY PLUG 3(IN SIDE)
      OUT     B804
21    LD      X644  ; PB.RESET (OP)
      OUT     B805
23    LDI     X641  ; SS.AUTO.MANUAL
      OUT     B806
      MPS
      INV
      OUT     M70  ; PL MANUAL
      MPP
      OUT     M71  ; PL AUTO
30    LD      X7  ; Emergency
      OUT     B807
32    LD      X8  ; Pressure Sensor
      OUT     B808
34    LD      X9  ; MASTER ON
      OUT     B809
36    LD      X0A  ; INV.1TRANSFER ERROR
      OUT     B80A
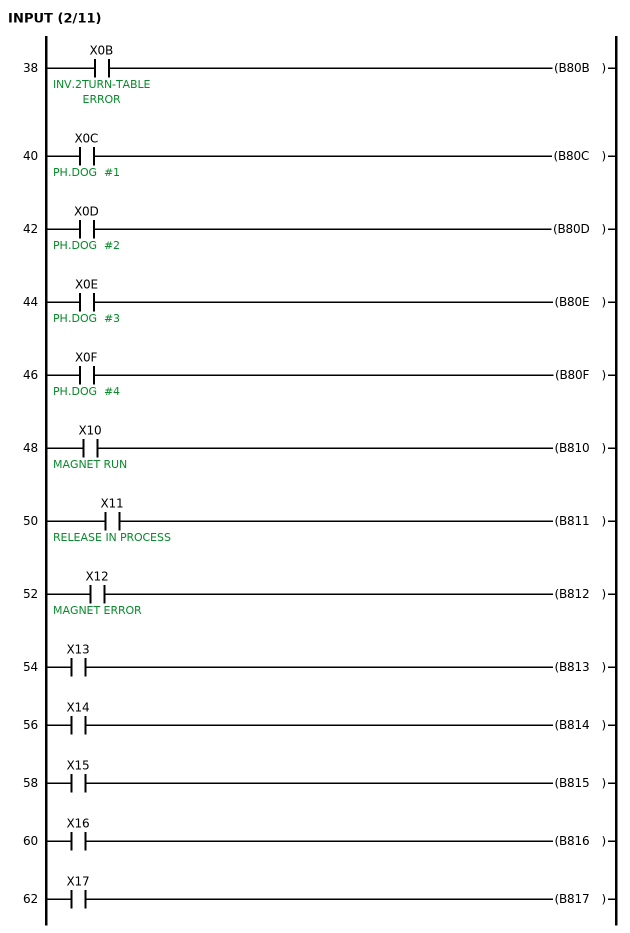
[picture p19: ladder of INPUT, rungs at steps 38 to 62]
38    LD      X0B  ; INV.2TURN-TABLE ERROR
      OUT     B80B
40    LD      X0C  ; PH.DOG  #1
      OUT     B80C
42    LD      X0D  ; PH.DOG  #2
      OUT     B80D
44    LD      X0E  ; PH.DOG  #3
      OUT     B80E
46    LD      X0F  ; PH.DOG  #4
      OUT     B80F
48    LD      X10  ; MAGNET RUN
      OUT     B810
50    LD      X11  ; RELEASE IN PROCESS
      OUT     B811
52    LD      X12  ; MAGNET ERROR
      OUT     B812
54    LD      X13
      OUT     B813
56    LD      X14
      OUT     B814
58    LD      X15
      OUT     B815
60    LD      X16
      OUT     B816
62    LD      X17
      OUT     B817
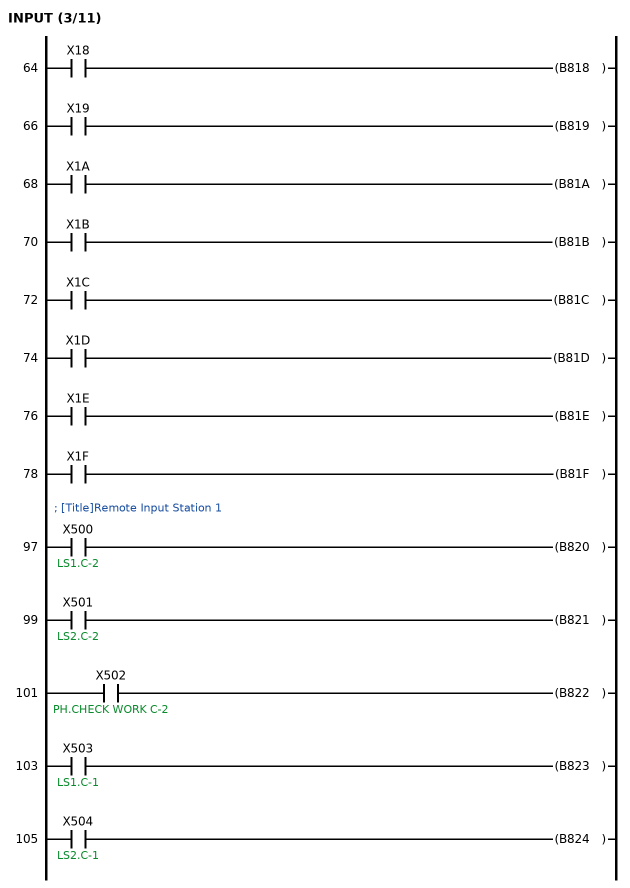
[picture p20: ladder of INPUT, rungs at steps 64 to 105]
64    LD      X18
      OUT     B818
66    LD      X19
      OUT     B819
68    LD      X1A
      OUT     B81A
70    LD      X1B
      OUT     B81B
72    LD      X1C
      OUT     B81C
74    LD      X1D
      OUT     B81D
76    LD      X1E
      OUT     B81E
78    LD      X1F
      OUT     B81F
; [Title]Remote Input Station 1
97    LD      X500  ; LS1.C-2
      OUT     B820
99    LD      X501  ; LS2.C-2
      OUT     B821
101   LD      X502  ; PH.CHECK WORK C-2
      OUT     B822
103   LD      X503  ; LS1.C-1
      OUT     B823
105   LD      X504  ; LS2.C-1
      OUT     B824
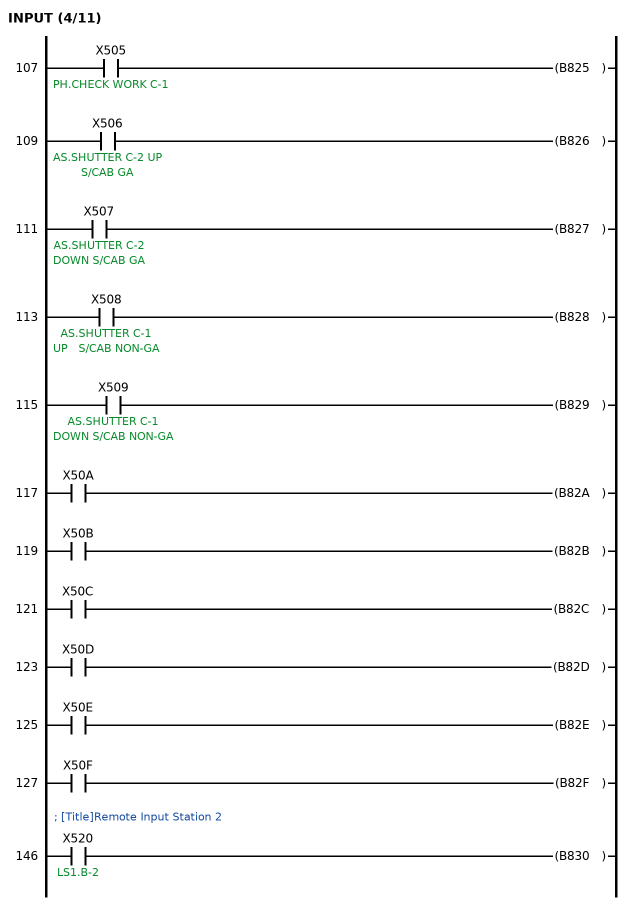
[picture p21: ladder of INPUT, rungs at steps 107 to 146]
107   LD      X505  ; PH.CHECK WORK C-1
      OUT     B825
109   LD      X506  ; AS.SHUTTER C-2 UP S/CAB GA
      OUT     B826
111   LD      X507  ; AS.SHUTTER C-2 DOWN S/CAB GA
      OUT     B827
113   LD      X508  ; AS.SHUTTER C-1 UP　S/CAB NON-GA
      OUT     B828
115   LD      X509  ; AS.SHUTTER C-1 DOWN S/CAB NON-GA
      OUT     B829
117   LD      X50A
      OUT     B82A
119   LD      X50B
      OUT     B82B
121   LD      X50C
      OUT     B82C
123   LD      X50D
      OUT     B82D
125   LD      X50E
      OUT     B82E
127   LD      X50F
      OUT     B82F
; [Title]Remote Input Station 2
146   LD      X520  ; LS1.B-2
      OUT     B830
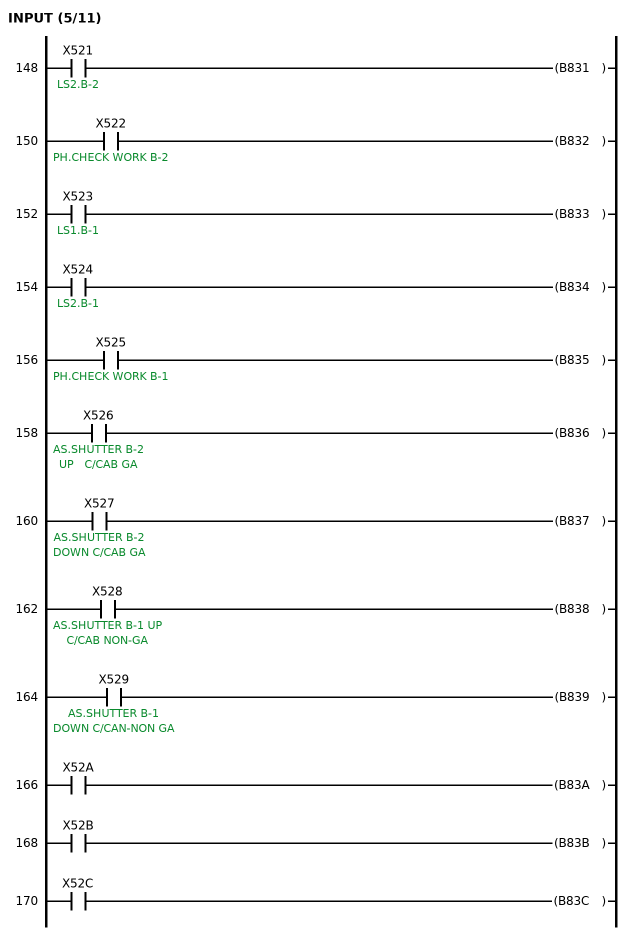
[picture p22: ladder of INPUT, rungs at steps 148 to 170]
148   LD      X521  ; LS2.B-2
      OUT     B831
150   LD      X522  ; PH.CHECK WORK B-2
      OUT     B832
152   LD      X523  ; LS1.B-1
      OUT     B833
154   LD      X524  ; LS2.B-1
      OUT     B834
156   LD      X525  ; PH.CHECK WORK B-1
      OUT     B835
158   LD      X526  ; AS.SHUTTER B-2 UP　C/CAB GA
      OUT     B836
160   LD      X527  ; AS.SHUTTER B-2 DOWN C/CAB GA
      OUT     B837
162   LD      X528  ; AS.SHUTTER B-1 UP C/CAB NON-GA
      OUT     B838
164   LD      X529  ; AS.SHUTTER B-1 DOWN C/CAN-NON GA
      OUT     B839
166   LD      X52A
      OUT     B83A
168   LD      X52B
      OUT     B83B
170   LD      X52C
      OUT     B83C
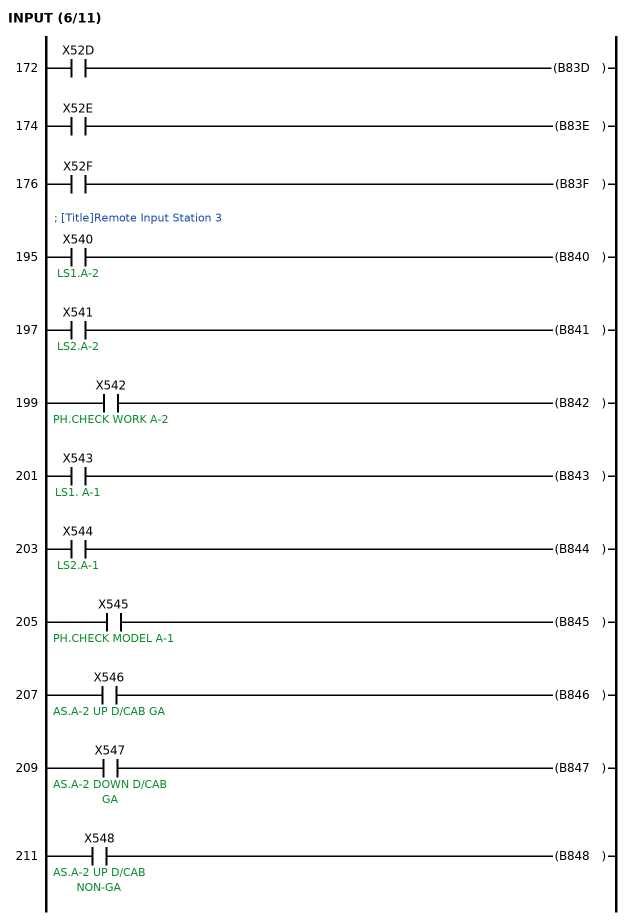
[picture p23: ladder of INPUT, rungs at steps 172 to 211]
172   LD      X52D
      OUT     B83D
174   LD      X52E
      OUT     B83E
176   LD      X52F
      OUT     B83F
; [Title]Remote Input Station 3
195   LD      X540  ; LS1.A-2
      OUT     B840
197   LD      X541  ; LS2.A-2
      OUT     B841
199   LD      X542  ; PH.CHECK WORK A-2
      OUT     B842
201   LD      X543  ; LS1. A-1
      OUT     B843
203   LD      X544  ; LS2.A-1
      OUT     B844
205   LD      X545  ; PH.CHECK MODEL A-1
      OUT     B845
207   LD      X546  ; AS.A-2 UP D/CAB GA
      OUT     B846
209   LD      X547  ; AS.A-2 DOWN D/CAB GA
      OUT     B847
211   LD      X548  ; AS.A-2 UP D/CAB NON-GA
      OUT     B848
213   LD      X549  ; AS.A-2 DOWN D/CAB NON-GA
      OUT     B849
215   LD      X54A
      OUT     B84A
217   LD      X54B
      OUT     B84B
219   LD      X54C  ; PB A-1
      OUT     B84C
221   LD      X54D
      OUT     B84D
223   LD      X54E
      OUT     B84E
225   LD      X54F
      OUT     B84F
; [Title]Remote Input Station 4
244   LD      X560  ; SCANNER S2
      OUT     B850
246   LD      X561
      OUT     B851
248   LD      X562  ; SCANNER S1
      OUT     B852
250   LD      X563  ; SCANNER C2
      OUT     B853
252   LD      X564
      OUT     B854
254   LD      X565
      OUT     B855
256   LD      X566
      OUT     B856
258   LD      X567
      OUT     B857
260   LD      X568
      OUT     B858
262   LD      X569
      OUT     B859
264   LD      X56A
      OUT     B85A
266   LD      X56B
      OUT     B85B
268   LD      X56C
      OUT     B85C
270   LD      X56D
      OUT     B85D
272   LD      X56E
      OUT     B85E
274   LD      X56F
      OUT     B85F
; [Title]Remote Input Station 5
293   LD      X580  ; LS RWD  Stop
      OUT     B860
295   LDI     B860
      AND     B861
      MEP
      RST     B861
299   LD      X581  ; LS RWD  Slow
      SET     B861
301   LD      X582  ; LS FWD  Slow    Speed
      SET     B862
303   LDI     B863
      AND     B862
      MEP
      RST     B862
307   LD      X583  ; LS FWD  Stop
      OUT     B863
309   LD      X58A  ; PX.TRUN CENTER
      OUT     B864
311   LD      X585  ; Px.Stop CCW
      OUT     B865
313   LD      X586  ; Px.Stop CW
      OUT     B866
315   LD      X587  ; PH.Check Work
      OUT     B867
317   LD      X588  ; AS.UNLOCK
      OUT     B868
319   LD      X589  ; AS LOCK
      OUT     B869
321   LD      X58A  ; PX.TRUN CENTER
      OUT     B86A
323   LD      X58B  ; SCANNER D1
      OUT     B86B
325   LD      X58C  ; SCANNER C1
      OUT     B86C
327   LD      X58D  ; SCANNER D2
      OUT     B86D
329   LD      X58E
      OUT     B86E
331   LD      X58F  ; LS STOP CENTER
      OUT     B86F
; [Title]Remote Input Station 6
350   LD      X5A0
      OUT     B870
352   LD      X5A1
      OUT     B871
354   LD      X5A2
      OUT     B872
356   LD      X5A3
      OUT     B873
358   LD      X5A4
      OUT     B874
360   LD      X5A5
      OUT     B875
362   LD      X5A6
      OUT     B876
364   LD      X5A7
      OUT     B877
366   LD      X5A8
      OUT     B878
368   LD      X5A9
      OUT     B879
370   LD      X5AA
      OUT     B87A
372   LD      X5AB
      OUT     B87B
374   LD      X5AC
      OUT     B87C
376   LD      X5AD
      OUT     B87D
378   LD      X5AE
      OUT     B87E
380   LD      X5AF
      OUT     B87F
382   END
END_PROGRAM

PROGRAM OUTPUT
0     LD      SM400
      LD      X2  ; SAFETY PLUG 1(OUT SIDE)
      AND     X3  ; SAFETY PLUG 2(OUT SIDE)
      ANI     X4  ; SAFETY PLUG 3(IN SIDE)
      LDI     X2  ; SAFETY PLUG 1(OUT SIDE)
      ANI     X3  ; SAFETY PLUG 2(OUT SIDE)
      AND     X4  ; SAFETY PLUG 3(IN SIDE)
      ORB
      ANB
      OUT     Y20  ; CR.PLC  RUN
10    LD      SM401  ; -
      OUT     Y21
12    LD      SM401  ; -
      OUT     Y22  ; PL.Reset
14    LD      X2  ; SAFETY PLUG 1(OUT SIDE)
      AND     X3  ; SAFETY PLUG 2(OUT SIDE)
      ANI     X4  ; SAFETY PLUG 3(IN SIDE)
      AND     X2  ; SAFETY PLUG 1(OUT SIDE)
      AND     X3  ; SAFETY PLUG 2(OUT SIDE)
      ANI     X4  ; SAFETY PLUG 3(IN SIDE)
      LDI     M81  ; Confirm Equipment Stop
      ANI     M80
      LD      M80
      AND     SM411
      ORB
      ANB
      LDI     X6  ; SS MAN/AUTO
      ANI     X2  ; SAFETY PLUG 1(OUT SIDE)
      ANI     X3  ; SAFETY PLUG 2(OUT SIDE)
      AND     X4  ; SAFETY PLUG 3(IN SIDE)
      AND     SM411
      AND     X9  ; MASTER ON
      ORB
      LD      M400  ; Auto Start Condition
      OR      M401  ; Auto Start Condition Transfer
      AND     M82  ; EQUIPMENT RUN
      ORB
      OUT     Y23  ; BUZZER
38    LD      X5  ; PB.Equipment Stop
      SET     M80
40    LD      M400  ; Auto Start Condition
      AND     M401  ; Auto Start Condition Transfer
      MEP
      SET     M82  ; EQUIPMENT RUN
44    LD      M80
      RST     M82  ; EQUIPMENT RUN
46    LD      M80
      MPS
      AND=    D104 K0  ; Transfer Unit
      ANI     X5C9  ; Model A-1 Inprocess
      ANI     X5CA  ; Model A-2 Inprocess
      ANI     X5CB  ; Model B-1 Inprocess
      ANI     X5CC  ; Model B-2 Inprocess
      ANI     X5CD  ; Model C-1 Inprocess
      ANI     X5CE  ; Model C-2 Inprocess
      OUT     T70 K50
      MPP
      RST     L100  ; ROBOT   ENABLE
63    LD      T70
      SET     M81  ; Confirm Equipment Stop
      RST     M80
      RST     M400  ; Auto Start Condition
      RST     M401  ; Auto Start Condition Transfer
68    LDI     X6  ; SS MAN/AUTO
      ANI     X2  ; SAFETY PLUG 1(OUT SIDE)
      ANI     X3  ; SAFETY PLUG 2(OUT SIDE)
      AND     X4  ; SAFETY PLUG 3(IN SIDE)
      OR      X6  ; SS MAN/AUTO
      MEP
      RST     M81  ; Confirm Equipment Stop
75    LD      B803
      ANI     T0
      LD<>    D11530 K100  ; Find Bit Fault
      AND<>   D421 K1000  ; Window Fault Cmd
      ORB
      OUT     M75  ; PL FAULT
85    LD      M299
      LD<>    D11530 K100  ; Find Bit Fault
      AND<>   D421 K1000  ; Window Fault Cmd
      AND     SM411
      ORB
      OUT     Y24  ; Tower   Lamp    Red
95    LDI     M299
      MPS
      LD      B806
      LD      SM412
      OR      T0
      ANB
      AND     SM412
      OR      M400  ; Auto Start Condition
      ANB
      OUT     Y25  ; Tower   Lamp    Green
      MPP
      ANI     B806
      AND     SM412
      OUT     Y26  ; Tower   Lamp    Yellow
109   LD      X640  ; PB.MASTER ON
      OUT     Y27  ; CR.MASTER ON
111   LD      X5E7  ; Magnet -ON
      OR      B0B12  ; MAGNET  -ON
      OUT     Y28  ; Magnet Attraction Signal
114   LD      X5E8
      OR      B0B12  ; MAGNET  -ON
      OUT     Y29  ; Magnet Attraction Voltage
117   LD      X5EA  ; Magnet Release
      OR      B0B13  ; MAGNET  -OFF
      OUT     Y2A  ; Magnet Release Signal
120   LD      SM401  ; -
      OUT     Y2B  ; Magnet Reset Signal
122   LD      X5C9  ; Model A-1 Inprocess
      AND     SM401  ; -
      LD      X5CA  ; Model A-2 Inprocess
      OR      X5CD  ; Model C-1 Inprocess
      OR      X5CE  ; Model C-2 Inprocess
      AND     SM401  ; -
      ORB
      OR      D300.0
      OUT     Y2C  ; Magnet Pattern 1
131   LD      X5CB  ; Model B-1 Inprocess
      AND     SM401  ; -
      LD      X5CC  ; Model B-2 Inprocess
      OR      X5CD  ; Model C-1 Inprocess
      OR      X5CE  ; Model C-2 Inprocess
      AND     SM401  ; -
      ORB
      OR      D300.1
      OUT     Y2D  ; Magnet Pattern 2
140   LD      D300.2
      OUT     Y2E  ; Magnet Pattern 4
142   LD      D300.3
      OUT     Y2F  ; Magnet Pattern 8
144   LD      W607.7
      LD      B90E
      OR      M2
      OR      X642  ; SS.ADV
      ANB
      ANI     B863
      LD      M263  ; ;Step 3 Motor FWD  HI Speed
      OR      M264  ; ;Step 4 Motor FWD Low Speed
      AND     M401  ; Auto Start Condition Transfer
      ORB
      ANI     X583  ; LS FWD  Stop
      OUT     Y30
156   LD      W607.7
      LD      B90F
      OR      X643  ; SS.RET
      ANB
      ANI     B860
      LD      M261  ; ;Step 1 Motor RWD
      OR      M270  ; ;Step 10 Motor RWD HI Speed
      OR      M271  ; ;Step 11 Motor RWD Low Speed
      OR      M274  ; Motor Rwd Hi
      AND     M401  ; Auto Start Condition Transfer
      ORB
      ANI     X580  ; LS RWD  Stop
      OUT     Y31
169   LD      B90E
      OR      B90F
      OR      M2
      OR      M261  ; ;Step 1 Motor RWD
      OR      M263  ; ;Step 3 Motor FWD  HI Speed
      OR      M264  ; ;Step 4 Motor FWD Low Speed
      OR      M270  ; ;Step 10 Motor RWD HI Speed
      OR      M271  ; ;Step 11 Motor RWD Low Speed
      OR      M274  ; Motor Rwd Hi
      OUT     Y32  ; Inv.1   Speed 1
179   LD      M301
      OR      B90E
      OR      B90F
      OR      M2
      ANI     B861
      ANI     B862
      OR      X642  ; SS.ADV
      OR      X643  ; SS.RET
      OR      M263  ; ;Step 3 Motor FWD  HI Speed
      OR      M270  ; ;Step 10 Motor RWD HI Speed
      OR      M274  ; Motor Rwd Hi
      OUT     Y33  ; Inv.1   Speed 2
191   LD      SM401  ; -
      OUT     Y35
193   LD      SM401  ; -
      OUT     Y36
195   LDI     M299
      ANI     B869
      AND     B868
      OR      M40  ; Turn CW
      OR      M41  ; Turn CCW
      OR      M42  ; ;Return CW
      OR      M43  ; ;Return CCW
      MPS
      LD      B910
      OR      B0B10  ; TURN ADV
      AND     W607.8
      LD      M40  ; Turn CW
      OR      M42  ; ;Return CW
      LD      M400  ; Auto Start Condition
      AND     M401  ; Auto Start Condition Transfer
      LDI     M400  ; Auto Start Condition
      ANI     M401  ; Auto Start Condition Transfer
      ORB
      ANB
      ORB
      ANB
      OUT     Y37  ; Inv.2 CW
      OUT     M90  ; Inv.2 CW
      MRD
      LD      B911
      OR      B0B11  ; TURN RET
      AND     W607.8
      LD      M41  ; Turn CCW
      OR      M43  ; ;Return CCW
      LD      M400  ; Auto Start Condition
      AND     M401  ; Auto Start Condition Transfer
      LDI     M400  ; Auto Start Condition
      ANI     M401  ; Auto Start Condition Transfer
      ORB
      ANB
      ORB
      ANB
      OUT     Y38  ; Inv.2   CCW
      OUT     M91  ; Inv.2 CcW
      MRD
      LD      B910
      OR      B911
      OR      B0B10  ; TURN ADV
      OR      B0B11  ; TURN RET
      OR      M40  ; Turn CW
      OR      M41  ; Turn CCW
      OR      M42  ; ;Return CW
      OR      M43  ; ;Return CCW
      ANB
      OUT     Y39  ; Inv2.   Speed 1
      MPP
      LD      M313
      OR      B910
      OR      B911
      ANB
      ANI     B862
      OUT     Y3A  ; Inv2.   Speed 2
252   LD      SM401  ; -
      OUT     Y3B
254   LD      SM401  ; -
      AND     M99
      OUT     Y3C
      OUT     Y3D
258   LD      SM401  ; -
      OUT     Y3E
260   LD      SM401  ; -
      OUT     Y3F
; Remote Output Station 1
276   LD      M55  ; C-2 PALLETE READY
      LDI     M811  ; C-2 LOAD-IN READY
      ANI     M55  ; C-2 PALLETE READY
      AND     SM412
      ORB
      LD      M810  ; C-2 REQUEST LOAD-IN
      OR      M811  ; C-2 LOAD-IN READY
      AND     SM411
      ORB
      OUT     Y510  ; PL C-2
286   LD      M54  ; C-1 PALLETE READY
      LDI     M809  ; C-1 LOAD-IN READY
      ANI     M54  ; C-1 PALLETE READY
      AND     SM412
      ORB
      LD      M808  ; C-1 REQUEST LOAD-IN
      OR      M809  ; C-1 LOAD-IN READY
      AND     SM411
      ORB
      OUT     Y511  ; PL C-1
296   LD      SM401  ; -
      OUT     Y512
298   LD      SM401  ; -
      OUT     Y513
300   LD      SM401  ; -
      OUT     Y514
302   LD      SM401  ; -
      OUT     Y515
304   LD      SM401  ; -
      OUT     Y516
306   LD      SM401  ; -
      OUT     Y517
308   LD      SM401  ; -
      OUT     Y518
310   LD      SM401  ; -
      OUT     Y519
312   LD      SM401  ; -
      OUT     Y51A
314   LD      SM401  ; -
      OUT     Y51B
316   LD      SM401  ; -
      OUT     Y51C
318   LD      SM401  ; -
      OUT     Y51D
320   LD      SM401  ; -
      OUT     Y51E
322   LD      SM401  ; -
      OUT     Y51F
; Remote Output Station 2
338   LD      M53  ; B-2 PALLETE READY
      LDI     M807  ; B-2 LOAD-IN READY
      ANI     M53  ; B-2 PALLETE READY
      AND     SM412
      ORB
      LD      M806  ; B-2 REQUEST LOAD-IN
      OR      M807  ; B-2 LOAD-IN READY
      AND     SM411
      ORB
      OUT     Y530  ; PL B-2
348   LD      M52  ; B-1 PALLETE READY
      LDI     M805  ; B-1 LOAD-IN READY
      ANI     M52  ; B-1 PALLETE READY
      AND     SM412
      ORB
      LD      M804  ; B-1 REQUEST LOAD-IN
      OR      M805  ; B-1 LOAD-IN READY
      AND     SM411
      ORB
      OUT     Y531  ; PL B-1
358   LD      SM401  ; -
      OUT     Y532
360   LD      SM401  ; -
      OUT     Y533
362   LD      SM401  ; -
      OUT     Y534
364   LD      SM401  ; -
      OUT     Y535
366   LD      SM401  ; -
      OUT     Y536
368   LD      SM401  ; -
      OUT     Y537
370   LD      SM401  ; -
      OUT     Y538
372   LD      SM401  ; -
      OUT     Y539
374   LD      SM401  ; -
      OUT     Y53A
376   LD      SM401  ; -
      OUT     Y53B
378   LD      SM401  ; -
      OUT     Y53C
380   LD      SM401  ; -
      OUT     Y53D
382   LD      SM401  ; -
      OUT     Y53E
384   LD      SM401  ; -
      OUT     Y53F
; Remote Output Station 3
400   LD      M51  ; A-2 PALLETE READY
      LDI     M803  ; A-2 LOAD-IN READY
      ANI     M51  ; A-2 PALLETE READY
      AND     SM412
      ORB
      LD      M802  ; A-2 REQUEST LOAD-IN
      OR      M803  ; A-2 LOAD-IN READY
      AND     SM411
      ORB
      OUT     Y550  ; PL A-2
410   LD      M50  ; A-1 PALLETE READY
      LDI     M801  ; A-1 LOAD-IN READY
      ANI     M50  ; A-1 PALLETE READY
      AND     SM412
      ORB
      LD      M800  ; A-1 REQUEST LOAD-IN
      OR      M801  ; A-1 LOAD-IN READY
      AND     SM411
      ORB
      OUT     Y551  ; PL A-1
420   LD      SM401  ; -
      OUT     Y552
422   LD      SM401  ; -
      OUT     Y553
424   LD      SM401  ; -
      OUT     Y554
426   LD      SM401  ; -
      OUT     Y555
428   LD      SM401  ; -
      OUT     Y556
430   LD      SM401  ; -
      OUT     Y557
432   LD      SM401  ; -
      OUT     Y558
434   LD      SM401  ; -
      OUT     Y559
436   LD      SM401  ; -
      OUT     Y55A
438   LD      SM401  ; -
      OUT     Y55B
440   LD      SM401  ; -
      OUT     Y55C
442   LD      SM401  ; -
      OUT     Y55D
444   LD      SM401  ; -
      OUT     Y55E
446   LD      SM401  ; -
      OUT     Y55F
; [Title]Remote Output Station 4
465   LDI     M299
      MPS
      AND     B0B00  ; SHUTTER C-2 UP
      ANI     B826
      OUT     Y570  ; SOL.SHUTTER UP C-2
      MRD
      AND     B0B01  ; SHUTTER C-2 DOWN
      ANI     B827
      OUT     Y571  ; SOL.SHUTTER DOWN C-2
      MRD
      AND     B0B02  ; SHUTTER C-1 UP
      ANI     B828
      OUT     Y572  ; SOL.SHUTTER UP C-1
      MRD
      AND     B0B03  ; SHUTTER C-1 DOWN
      ANI     B829
      OUT     Y573  ; SOL.SHUTTER DOWN C-1
      MRD
      AND     B0B04  ; SHUTTER B-2 UP
      ANI     B836
      OUT     Y574  ; SOL.SHUTTER UP B-2
      MRD
      AND     B0B05  ; SHUTTER B-2 DOWN
      ANI     B837
      OUT     Y575  ; SOL.SHUTTER DOWN B-2
      MRD
      AND     B0B06  ; SHUTTER B-1 UP
      ANI     B838
      OUT     Y576  ; SOL.SHUTTER UP B-1
      MRD
      AND     B0B07  ; SHUTTER B-1 DOWN
      ANI     B839
      OUT     Y577  ; SOL.SHUTTER DOWN B-1
      MRD
      AND     B0B08  ; SHUTTER A-2 UP
      ANI     B846
      OUT     Y578  ; SOL.SHUTTER UP A-2
      MRD
      AND     B0B09  ; SHUTTER A-2 DOWN
      ANI     B847
      OUT     Y579  ; SOL.SHUTTER DOWN A-1
      MRD
      AND     B0B0A  ; SHUTTER UP
      ANI     B848
      OUT     Y57A  ; SOL.SHUTTER UP A-1
      MRD
      AND     B0B0B  ; SHUTTER DOWN
      ANI     B849
      OUT     Y57B  ; SOL.SHUTTER DOWN A-1
      MRD
      LD      B0B0C  ; TURN LOCK
      LD      B860
      AND     B864
      AND     T0
      ORB
      LD      M44  ; Lock    Turn
      ANI     W607.6
      ORB
      ANB
      OUT     Y57C  ; Sol.Turn Table  Lock
      MPP
      LD      B0B0D  ; TURN UNLOCK
      LDI     B860
      AND     T0
      ORB
      LDI     M44  ; Lock    Turn
      ANI     W607.6
      ORB
      ANB
      OUT     Y57D  ; Sol.Turn Table  Unlock
535   LD      SM401  ; -
      OUT     Y57E
537   LD      SM401  ; -
      OUT     Y57F
; [Title]Remote Output Station 5
556   LD      M268  ; ;Step 8 Wait Pick complete
      AND     X586  ; Px.Stop CW
      AND     SM411
      OUT     Y590  ; Lamp Status Ok 1(Left)
560   LD      M268  ; ;Step 8 Wait Pick complete
      AND     X585  ; Px.Stop CCW
      AND     SM411
      OUT     Y591  ; Lamp Status Ok 2(Right)
564   LD      SM401  ; -
      OUT     Y592
566   LD      SM401  ; -
      OUT     Y593
568   LD      SM401  ; -
      OUT     Y594
570   LD      SM401  ; -
      OUT     Y595
572   LD      SM401  ; -
      OUT     Y596
574   LD      SM401  ; -
      OUT     Y597
576   LD      SM401  ; -
      OUT     Y598
578   LD      SM401  ; -
      OUT     Y599
580   LD      SM401  ; -
      OUT     Y59A
582   LD      SM401  ; -
      OUT     Y59B
584   LD      SM401  ; -
      OUT     Y59C
586   LD      SM401  ; -
      OUT     Y59D
588   LD      SM401  ; -
      OUT     Y59E
590   LD      SM401  ; -
      OUT     Y59F
; [Title]Remote Output Station 6
609   LD      X7  ; Emergency
      AND     X9  ; MASTER ON
      OUT     Y5B0  ; CR.EMERGENCY ROBOT
612   LD      SM401  ; -
      OUT     Y5B1
614   LD      SM401  ; -
      OUT     Y5B2
616   LD      SM401  ; -
      OUT     Y5B3
618   LD      SM400
      OUT     Y5B4  ; CR.Safety plug  Robot
620   LD      SM401  ; -
      OUT     Y5B5
622   LD      SM401  ; -
      OUT     Y5B6
624   LD      SM401  ; -
      OUT     Y5B7
626   LD      SM401  ; -
      OUT     Y5B8
628   LD      SM401  ; -
      OUT     Y5B9
630   LD      SM401  ; -
      OUT     Y5BA
632   LD      SM401  ; -
      OUT     Y5BB
634   LD      SM401  ; -
      OUT     Y5BC
636   LD      SM401  ; -
      OUT     Y5BD
638   LD      SM401  ; -
      OUT     Y5BE
640   LD      SM401  ; -
      OUT     Y5BF
; [Title]REMOTE OP ST11
655   LD      X9  ; MASTER ON
      OUT     Y650  ; PL.MASTER ON
657   LD      X641  ; SS.AUTO.MANUAL
      AND     SM412
      ORI     X641  ; SS.AUTO.MANUAL
      AND     X9  ; MASTER ON
      OUT     Y651  ; PL.SS AUTO/ MANUAL
662   LD<>    D11530 K100  ; Find Bit Fault
      AND<>   D421 K1000  ; Window Fault Cmd
      AND     SM411
      OUT     Y652  ; PL.RESET
670   LD      SM401  ; -
      OUT     Y653  ; PL.WELD OFF
672   LD      L103  ; RB.HOLD CONFIRM
      AND     SM412
      OUT     Y654  ; PL.HOLD
675   LD      SM401  ; -
      OUT     Y655  ; PL.TRIP DRESS
677   LD<>    D11530 K100  ; Find Bit Fault
      AND<>   D421 K1000  ; Window Fault Cmd
      OUT     Y656  ; BUZZER
684   LD      M71  ; PL AUTO
      ANI     M400  ; Auto Start Condition
      OUT     Y657  ; PL.AUTO STOP
687   LD      M71  ; PL AUTO
      LD      M400  ; Auto Start Condition
      AND     M401  ; Auto Start Condition Transfer
      OR      SM411
      ANB
      OUT     Y658  ; PL.AUTO START
693   END
END_PROGRAM

PROGRAM ALARM
; [Title]All Alarm
10    LD      B82B
      AND     B82D
      AND     B83B
      AND     B83D
      AND     B84B
      AND     B84D
      MEF
      SET     M299
18    LD      B805
      AND     M299
      RST     M299
21    LD      SM401  ; -
      SET     M7700  ; NOT USE
23    LDI     X7  ; Emergency
      SET     M7701  ; EMERGENCY STOP
25    LDI     X8  ; Pressure Sensor
      SET     M7702  ; AIR PRESSURE LOW
27    LD      X0A  ; INV.1TRANSFER ERROR
      SET     M7703  ; INVERTER TRANSFER ABNORMAL
29    LD      X0B  ; INV.2TURN-TABLE ERROR
      SET     M7704  ; INVERTER TURNTABLE ABNORMAL
31    LD      X5D7  ; ROBOT EMERGENCY
      SET     M7705  ; ROBOT EMERGENCY STOP
33    LD      SM400
      LD      X5D4  ; Error   Port
      OR      X5D6  ; ROBOT ALARM PORT ERROR
      OR      X5DF  ; Information port
      ANB
      SET     M7706  ; ROBOT ABNORMAL
39    LD      SM401  ; -
      SET     M7707
41    LD      SM401  ; -
      SET     M7708
43    LD      SM401  ; -
      SET     M7709
45    LD      SM400
      AND     M400  ; Auto Start Condition
      AND     M401  ; Auto Start Condition Transfer
      ANI     M268  ; ;Step 8 Wait Pick complete
      ANI     X0  ; Light Curtain (1)Left
      MPS
      AND     T1000
      SET     M7710  ; LIGHT CURTAIN LEFT ABNORMAL
      RST     M401  ; Auto Start Condition Transfer
      MPP
      OUT     T1000 K0
59    LD      SM400
      AND     M400  ; Auto Start Condition
      AND     M401  ; Auto Start Condition Transfer
      ANI     M268  ; ;Step 8 Wait Pick complete
      ANI     X1  ; Light Curtain (2) Right
      MPS
      AND     T1001
      SET     M7711  ; LIGHT CURTAIN RIGHT ABNORMAL
      RST     M401  ; Auto Start Condition Transfer
      MPP
      OUT     T1001 K0
73    LD      Y57A  ; SOL.SHUTTER UP A-1
      MPS
      AND     T1002
      SET     M7712  ; SHUTTER A-1 UP ABNORMAL
      MPP
      OUT     T1002 K50
82    LD      Y57B  ; SOL.SHUTTER DOWN A-1
      MPS
      AND     T1003
      SET     M7713  ; SHUTTER A-1 DOWN ABNORMAL
      MPP
      OUT     T1003 K50
91    LD      Y578  ; SOL.SHUTTER UP A-2
      MPS
      AND     T1004
      SET     M7714  ; SHUTTER A-2 UP ABNORMAL
      MPP
      OUT     T1004 K50
100   LD      Y579  ; SOL.SHUTTER DOWN A-1
      MPS
      AND     T1005
      SET     M7715  ; SHUTTER A-2 DOWN ABNORMAL
      MPP
      OUT     T1005 K50
109   LD      Y576  ; SOL.SHUTTER UP B-1
      MPS
      AND     T1006
      SET     M7716  ; SHUTTER B-1 UP ABNORMAL
      MPP
      OUT     T1006 K50
118   LD      Y577  ; SOL.SHUTTER DOWN B-1
      MPS
      AND     T1007
      SET     M7717  ; SHUTTER B-1 DOWN ABNORMAL
      MPP
      OUT     T1007 K50
127   LD      Y574  ; SOL.SHUTTER UP B-2
      MPS
      AND     T1008
      SET     M7718  ; SHUTTER B-2 UP ABNORMAL
      MPP
      OUT     T1008 K50
136   LD      Y575  ; SOL.SHUTTER DOWN B-2
      MPS
      AND     T1009
      SET     M7719  ; SHUTTER B-2 DOWN ABNORMAL
      MPP
      OUT     T1009 K50
145   LD      Y572  ; SOL.SHUTTER UP C-1
      MPS
      AND     T1010
      SET     M7720  ; SHUTTER C-1 UP ABNORMAL
      MPP
      OUT     T1010 K50
154   LD      Y573  ; SOL.SHUTTER DOWN C-1
      MPS
      AND     T1011
      SET     M7721  ; SHUTTER C-1 DOWN ABNORMAL
      MPP
      OUT     T1011 K50
163   LD      Y570  ; SOL.SHUTTER UP C-2
      MPS
      AND     T1012
      SET     M7722  ; SHUTTER C-2 UP ABNORMAL
      MPP
      OUT     T1012 K50
172   LD      Y571  ; SOL.SHUTTER DOWN C-2
      MPS
      AND     T1013
      SET     M7723  ; SHUTTER C-2 DOWN ABNORMAL
      MPP
      OUT     T1013 K50
181   LD      SM401  ; -
      AND     M400  ; Auto Start Condition
      SET     M7724  ; SAFETY SCANNER 1 WRANING
184   LD      SM401  ; -
      AND     M400  ; Auto Start Condition
      SET     M7725  ; SAFETY SCANNER 1 ABNORMAL
187   LD      SM401  ; -
      AND     M400  ; Auto Start Condition
      SET     M7726  ; SAFETY SCANNER 2 WRANING
190   LD      SM401  ; -
      AND     M400  ; Auto Start Condition
      SET     M7727  ; SAFETY SCANNER 2 ABNORMAL
193   LDF     M50  ; A-1 PALLETE READY
      AND     M400  ; Auto Start Condition
      SET     M7728  ; PALLETE MODEL A-1 EMPTY
197   LDF     M51  ; A-2 PALLETE READY
      AND     M400  ; Auto Start Condition
      SET     M7729  ; PALLETE MODEL A-2 EMPTY
201   LDF     M52  ; B-1 PALLETE READY
      AND     M400  ; Auto Start Condition
      SET     M7730  ; PALLETE MODEL B-1 EMPTY
205   LDF     M53  ; B-2 PALLETE READY
      AND     M400  ; Auto Start Condition
      SET     M7731  ; PALLETE MODEL B-2 EMPTY
209   LDF     M54  ; C-1 PALLETE READY
      AND     M400  ; Auto Start Condition
      SET     M7732  ; PALLETE MODEL C-1 EMPTY
213   LDF     M55  ; C-2 PALLETE READY
      AND     M400  ; Auto Start Condition
      SET     M7733  ; PALLETE MODEL C-2 EMPTY
217   LD      M71  ; PL AUTO
      OR      M460
      MPS
      ANI     X58B  ; SCANNER D1
      ANI     M263  ; ;Step 3 Motor FWD  HI Speed
      ANI     M264  ; ;Step 4 Motor FWD Low Speed
      ANI     M450  ; INTERUP D/CAB NOT PLATE
      ANI     M455  ; INTERUP S/CAB  PLATED
      ANI     X5EB  ; Drop Zone
      LD      M76  ; PL MODEL A INPROCESS
      OR      M77  ; PL MODEL B INPROCESS
      OR      M78  ; PL MODELCB INPROCESS
      ANB
      SET     M7734  ; SCANNER D/CAB NOT PLATE
      MPP
      AND     X5C9  ; Model A-1 Inprocess
      AND     X5E1  ; Test    Interupt
      OUT     M450  ; INTERUP D/CAB NOT PLATE
235   LD      M71  ; PL AUTO
      OR      M460
      MPS
      ANI     X58D  ; SCANNER D2
      ANI     M450  ; INTERUP D/CAB NOT PLATE
      ANI     M451  ; INTERUP D/CAB PLATED
      MPS
      AND     T50
      SET     M7735  ; SCANNER D/CAB PLATE
      MPP
      LD      M76  ; PL MODEL A INPROCESS
      OR      M77  ; PL MODEL B INPROCESS
      OR      M78  ; PL MODELCB INPROCESS
      ANB
      OUT     T80 K5
      MPP
      AND     X5CA  ; Model A-2 Inprocess
      AND     X5E1  ; Test    Interupt
      OUT     M451  ; INTERUP D/CAB PLATED
257   LD      M71  ; PL AUTO
      OR      M460
      MPS
      ANI     X58C  ; SCANNER C1
      ANI     M451  ; INTERUP D/CAB PLATED
      ANI     M452  ; INTERUP C/CAB NOT PLATED
      MPS
      AND     T81
      SET     M7736  ; SCANNER C/CAB NOT PLATE
      MPP
      LD      M76  ; PL MODEL A INPROCESS
      OR      M77  ; PL MODEL B INPROCESS
      OR      M78  ; PL MODELCB INPROCESS
      ANB
      OUT     T81 K4
      MPP
      AND     X5CB  ; Model B-1 Inprocess
      AND     X5E1  ; Test    Interupt
      OUT     M452  ; INTERUP C/CAB NOT PLATED
279   LD      M71  ; PL AUTO
      OR      M460
      MPS
      ANI     X563  ; SCANNER C2
      ANI     M454  ; INTERUP S/CAB NOT PLATED
      ANI     M452  ; INTERUP C/CAB NOT PLATED
      ANI     M453  ; INTERUP C/CAB PLATED
      MPS
      AND     T83
      SET     M7737  ; SCANNER C/CAB  PLATE
      MPP
      LD      M76  ; PL MODEL A INPROCESS
      OR      M77  ; PL MODEL B INPROCESS
      OR      M78  ; PL MODELCB INPROCESS
      ANB
      OUT     T83 K3
      MPP
      AND     X5CC  ; Model B-2 Inprocess
      AND     X5E1  ; Test    Interupt
      OUT     M453  ; INTERUP C/CAB PLATED
302   LD      M71  ; PL AUTO
      OR      M460
      MPS
      ANI     X562  ; SCANNER S1
      ANI     M453  ; INTERUP C/CAB PLATED
      ANI     M454  ; INTERUP S/CAB NOT PLATED
      MPS
      AND     T84
      SET     M7738  ; SCANNER S/CAB NOT PLATE
      MPP
      LD      M76  ; PL MODEL A INPROCESS
      OR      M77  ; PL MODEL B INPROCESS
      OR      M78  ; PL MODELCB INPROCESS
      ANB
      OUT     T84 K5
      MPP
      AND     X5CD  ; Model C-1 Inprocess
      AND     X5E1  ; Test    Interupt
      OUT     M454  ; INTERUP S/CAB NOT PLATED
324   LD      M71  ; PL AUTO
      OR      M460
      MPS
      ANI     X560  ; SCANNER S2
      ANI     M263  ; ;Step 3 Motor FWD  HI Speed
      ANI     M264  ; ;Step 4 Motor FWD Low Speed
      ANI     M454  ; INTERUP S/CAB NOT PLATED
      ANI     M455  ; INTERUP S/CAB  PLATED
      MPS
      AND     T82
      SET     M7739  ; SCANNER S/CAB  PLATE
      MPP
      LD      M76  ; PL MODEL A INPROCESS
      OR      M77  ; PL MODEL B INPROCESS
      OR      M78  ; PL MODELCB INPROCESS
      ANB
      OUT     T82 K5
      MPP
      AND     X5CE  ; Model C-2 Inprocess
      AND     X5E1  ; Test    Interupt
      OUT     M455  ; INTERUP S/CAB  PLATED
348   LD      SM401  ; -
      SET     M7740
350   LD      SM401  ; -
      SET     M7741
352   LD      SM401  ; -
      SET     M7742
354   LD      X548  ; AS.A-2 UP D/CAB NON-GA
      ANI     X549  ; AS.A-2 DOWN D/CAB NON-GA
      OUT     M470  ; D/CAB_(NON GA)Light Curten Moni.
357   LD      X664  ; D/CAB_(NON GA)  Light Curten OK1
      AND     X665  ; D/CAB_(NON GA)  Light Curten OK2
      OUT     M471  ; D/CAB_(NON GA)  Light Curten OK
360   LD      M470  ; D/CAB_(NON GA)Light Curten Moni.
      ANI     M471  ; D/CAB_(NON GA)  Light Curten OK
      AND     X2  ; SAFETY PLUG 1(OUT SIDE)
      AND     X3  ; SAFETY PLUG 2(OUT SIDE)
      ANI     X4  ; SAFETY PLUG 3(IN SIDE)
      SET     M7744  ; D/CAB(NON-GA)LIGHT CURTAIN DETEC
366   LD      X546  ; AS.A-2 UP D/CAB GA
      ANI     X547  ; AS.A-2 DOWN D/CAB GA
      OUT     M472  ; D/CAB_  (GA)Light Curten Monitor
369   LD      X662  ; D/CAB_  (GA)    Light Curten OK1
      AND     X663  ; D/CAB_  (GA)    Light Curten OK2
      OUT     M473  ; D/CAB_  (GA)    Light Curten OK
372   LD      M472  ; D/CAB_  (GA)Light Curten Monitor
      ANI     M473  ; D/CAB_  (GA)    Light Curten OK
      AND     X2  ; SAFETY PLUG 1(OUT SIDE)
      AND     X3  ; SAFETY PLUG 2(OUT SIDE)
      ANI     X4  ; SAFETY PLUG 3(IN SIDE)
      SET     M7745  ; D/CAB(GA)LIGHT  CURTAIN DETECTIO
378   LD      X528  ; AS.SHUTTER B-1 UP C/CAB NON-GA
      ANI     X529  ; AS.SHUTTER B-1 DOWN C/CAN-NON GA
      OUT     M474  ; C/CAB_(NON GA)Light Curten Moni.
381   LD      X660  ; C/CAB_(NON GA)  Light Curten OK1
      AND     X661  ; C/CAB_(NON GA)  Light Curten OK2
      OUT     M475  ; C/CAB_(NON GA)  Light Curten OK
384   LD      M474  ; C/CAB_(NON GA)Light Curten Moni.
      ANI     M475  ; C/CAB_(NON GA)  Light Curten OK
      AND     X2  ; SAFETY PLUG 1(OUT SIDE)
      AND     X3  ; SAFETY PLUG 2(OUT SIDE)
      ANI     X4  ; SAFETY PLUG 3(IN SIDE)
      SET     M7746  ; C/CAB(NON-GA)LIGHT CURTAIN DETEC
390   LD      X526  ; AS.SHUTTER B-2 UP　C/CAB GA
      ANI     X527  ; AS.SHUTTER B-2 DOWN C/CAB GA
      OUT     M476  ; C/CAB_  (GA)Light Curten Monitor
393   LD      X666  ; C/CAB_  (GA)    Light Curten OK1
      AND     X667  ; C/CAB_  (GA)    Light Curten OK2
      OUT     M477  ; C/CAB_  (GA)    Light Curten OK
396   LD      M476  ; C/CAB_  (GA)Light Curten Monitor
      ANI     M477  ; C/CAB_  (GA)    Light Curten OK
      AND     X2  ; SAFETY PLUG 1(OUT SIDE)
      AND     X3  ; SAFETY PLUG 2(OUT SIDE)
      ANI     X4  ; SAFETY PLUG 3(IN SIDE)
      SET     M7747  ; C/CAB(GA)LIGHT  CURTAIN DETECTIO
402   LD      X508  ; AS.SHUTTER C-1 UP　S/CAB NON-GA
      ANI     X509  ; AS.SHUTTER C-1 DOWN S/CAB NON-GA
      OUT     M478  ; S/CAB_(NON GA)Light Curten Moni.
405   LD      X668  ; S/CAB_(NON GA)  Light Curten OK1
      AND     X669  ; S/CAB_(NON GA)  Light Curten OK2
      OUT     M479  ; S/CAB_(NON GA)  Light Curten OK
408   LD      M478  ; S/CAB_(NON GA)Light Curten Moni.
      ANI     M479  ; S/CAB_(NON GA)  Light Curten OK
      AND     X2  ; SAFETY PLUG 1(OUT SIDE)
      AND     X3  ; SAFETY PLUG 2(OUT SIDE)
      ANI     X4  ; SAFETY PLUG 3(IN SIDE)
      SET     M7748  ; S/CAB(NON-GA)LIGHT CURTAIN DETEC
414   LD      X506  ; AS.SHUTTER C-2 UP S/CAB GA
      ANI     X507  ; AS.SHUTTER C-2 DOWN S/CAB GA
      OUT     M480  ; S/CAB_  (GA)Light Curten Monitor
417   LD      X66A  ; S/CAB_  (GA)    Light Curten OK1
      AND     X66B  ; S/CAB_  (GA)    Light Curten OK2
      OUT     M481  ; S/CAB_  (GA)    Light Curten OK
420   LD      M480  ; S/CAB_  (GA)Light Curten Monitor
      ANI     M481  ; S/CAB_  (GA)    Light Curten OK
      AND     X2  ; SAFETY PLUG 1(OUT SIDE)
      AND     X3  ; SAFETY PLUG 2(OUT SIDE)
      ANI     X4  ; SAFETY PLUG 3(IN SIDE)
      SET     M7749  ; S/CAB(GA)LIGHT  CURTAIN DETECTIO
426   LD      M7911
      OR      M7914
      CJ      P0
430   LD      SM400
      MOV     K0 D11530  ; Find Bit Fault
      MOV     K0 Z11
      MOV     K0 Z12
437   FOR     K100
439   LD      M7912
      AND=    D11530 D11531  ; Find Bit Fault
      MPS
      ANI     M7700Z12
      SET     M7914
      MPP
      BREAK   D11522 P0
451   LDI     M7912
      AND     M7700Z12
      LD>     D11530 D11531  ; Find Bit Fault
      OR=     D11531 K9999
      ANB
      BMOV    D10000Z11 D11505 K20
      SET     M7913
      MOV     D11530 D11531
      BREAK   D11522 P0
472   LD      SM400
      +       Z11 K20 Z11
      +       Z12 K1 Z12
      INC     D11530
481   LD>=    D11530 K100  ; Find Bit Fault
      MOV     K9999 D11531
486   NEXT
; [Title]Alarm found Timing
      P0
503   LDP     M7913
      OR      M7912
      ANI     T1950  ; Time Show Fault Window
      ANI     M7914
      OUT     M7912
      RST     M7913
      OUT     T1950 K20  ; Time Show Fault Window
; [Title]RESET
522   LD      X644  ; PB.RESET (OP)
      MOV     K0 D11522
      MOV     K0 D11530
      MOV     K0 D11531
      RST     M7914
      BKRST   M7700 K150
533   LDI     M7700Z12
      RST     M7914
; [Title]WINDOWS FAULT
548   LD      SM400
      MPS
      AND<>   D11530 K100  ; Find Bit Fault
      MOV     D11530 D6004  ; Source Bit Fault
      MRD
      AND=    D11530 K100  ; Find Bit Fault
      MOV     K0 D6004
      MOV     K0 D1  ; Window Fault TP
      MPP
      -       D6004 K0 D6005  ; Confirm Fault
      +       D6005 K1000 D421  ; Window Fault Cmd
570   LD      SM400
      MPS
      AND<>   D6005 K0  ; Confirm Fault
      MOV     K1 D420
      MRD
      AND=    D6005 K0  ; Confirm Fault
      MOV     K0 D420
      MPP
      MOV     K150 D422
      MOV     K140 D423
      AND<>   D11530 K100  ; Find Bit Fault
      AND<>   D421 K1000  ; Window Fault Cmd
      MOV     D421 D1
596   END
END_PROGRAM

PROGRAM AUTO_1
0     LD      SM400
      DECO    D100 M100 K5
; [Title]Start Step
16    LD      M100
      ANI     SM401  ; -
      MOV     K1 D100
; [Title]Step 1
29    LD      M101
      OUT     T101 K10
      AND     T101
      MOV     K2 D100
37    LD      M102
      OUT     T102 K10
      AND     T102
      MOV     K3 D100
45    LD      M103
      OUT     T103 K10
      AND     T103
      MOV     K4 D100
53    LD      M104
      OUT     T104 K10
      AND     T104
      MOV     K5 D100
61    LD      M105
      OUT     T105 K10
      AND     T105
      MOV     K6 D100
69    LD      M106
      OUT     T106 K10
      AND     T106
      MOV     K7 D100
77    LD      M107
      OUT     T107 K10
      AND     T107
      MOV     K8 D100
85    LD      M108
      OUT     T108 K10
      AND     T108
      MOV     K9 D100
93    LD      M109
      OUT     T109 K10
      AND     T109
      MOV     K10 D100
101   LD      M110
      OUT     T110 K10
      AND     T110
      MOV     K11 D100
109   LD      M111
      OUT     T111 K10
      AND     T111
      MOV     K12 D100
117   LD      M112
      OUT     T112 K10
      AND     T112
      MOV     K13 D100
125   LD      M113
      OUT     T113 K10
      AND     T113
      MOV     K14 D100
133   LD      M114
      OUT     T114 K10
      AND     T114
      MOV     K15 D100
141   LD      M115
      OUT     T115 K10
      AND     T115
      MOV     K16 D100
149   LD      M116
      OUT     T116 K10
      AND     T116
      MOV     K17 D100
157   LD      M117
      OUT     T117 K10
      AND     T117
      MOV     K18 D100
165   LD      M118
      OUT     T118 K10
      AND     T118
      MOV     K19 D100
173   LD      M119
      OUT     T119 K10
      AND     T119
      MOV     K20 D100
181   LD      M120
      OUT     T120 K10
      AND     T120
      MOV     K21 D100
189   LD      M121
      OUT     T121 K10
      AND     T121
      MOV     K22 D100
197   LD      M122
      OUT     T122 K10
      AND     T122
      MOV     K23 D100
205   LD      M123
      OUT     T123 K10
      AND     T123
      MOV     K24 D100
213   LD      M124
      OUT     T124 K10
      AND     T124
      MOV     K25 D100
221   LD      M125
      OUT     T125 K10
      AND     T125
      MOV     K26 D100
229   LD      M126
      OUT     T126 K10
      AND     T126
      MOV     K27 D100
237   LD      M127
      OUT     T127 K10
      AND     T127
      MOV     K28 D100
245   LD      M128
      OUT     T128 K10
      AND     T128
      MOV     K29 D100
253   LD      M129
      OUT     T129 K10
      AND     T129
      MOV     K30 D100
261   LD      M130
      OUT     T130 K10
      AND     T130
      MOV     K31 D100
269   LD      M131
      OUT     T131 K10
      AND     T131
      MOV     K0 D100
277   END
END_PROGRAM

PROGRAM AUTO_2
0     LD      SM400
      DECO    D101 M140 K5
; [Title]Start Step
16    LD      M140
      ANI     SM401  ; -
      MOV     K1 D101
; [Title]Step 1
29    LD      M141
      OUT     T141 K10
      AND     T141
      MOV     K2 D101
37    LD      M142
      OUT     T142 K10
      AND     T142
      MOV     K3 D101
45    LD      M143
      OUT     T143 K10
      AND     T143
      MOV     K4 D101
53    LD      M144
      OUT     T144 K10
      AND     T144
      MOV     K5 D101
61    LD      M145
      OUT     T145 K10
      AND     T145
      MOV     K6 D101
69    LD      M146
      OUT     T146 K10
      AND     T146
      MOV     K7 D101
77    LD      M147
      OUT     T147 K10
      AND     T147
      MOV     K8 D101
85    LD      M148
      OUT     T148 K10
      AND     T148
      MOV     K9 D101
93    LD      M149
      OUT     T149 K10
      AND     T149
      MOV     K10 D101
101   LD      M150
      OUT     T150 K10
      AND     T150
      MOV     K11 D101
109   LD      M151
      OUT     T151 K10
      AND     T151
      MOV     K12 D101
117   LD      M152
      OUT     T152 K10
      AND     T152
      MOV     K13 D101
125   LD      M153
      OUT     T153 K10
      AND     T153
      MOV     K14 D101
133   LD      M154
      OUT     T154 K10
      AND     T154
      MOV     K15 D101
141   LD      M155
      OUT     T155 K10
      AND     T155
      MOV     K16 D101
149   LD      M156
      OUT     T156 K10
      AND     T156
      MOV     K17 D101
157   LD      M157
      OUT     T157 K10
      AND     T157
      MOV     K18 D101
165   LD      M158
      OUT     T158 K10
      AND     T158
      MOV     K19 D101
173   LD      M159
      OUT     T159 K10
      AND     T159
      MOV     K20 D101
181   LD      M160
      OUT     T160 K10
      AND     T160
      MOV     K21 D101
189   LD      M161
      OUT     T161 K10
      AND     T161
      MOV     K22 D101
197   LD      M162
      OUT     T162 K10
      AND     T162
      MOV     K23 D101
205   LD      M163
      OUT     T163 K10
      AND     T163
      MOV     K24 D101
213   LD      M164
      OUT     T164 K10
      AND     T164
      MOV     K25 D101
221   LD      M165
      OUT     T165 K10
      AND     T165
      MOV     K26 D101
229   LD      M166
      OUT     T166 K10
      AND     T166
      MOV     K27 D101
237   LD      M167
      OUT     T167 K10
      AND     T167
      MOV     K28 D101
245   LD      M168
      OUT     T168 K10
      AND     T168
      MOV     K29 D101
253   LD      M169
      OUT     T169 K10
      AND     T169
      MOV     K30 D101
261   LD      M170
      OUT     T170 K10
      AND     T170
      MOV     K31 D101
269   LD      M171
      OUT     T171 K10
      AND     T171
      MOV     K0 D101
277   END
END_PROGRAM

PROGRAM AUTO_3
0     LD      SM400
      DECO    D102 M180 K5
; [Title]Start Step
16    LD      M180
      ANI     SM401  ; -
      MOV     K1 D102
; [Title]Step 1
29    LD      M181
      OUT     T181 K10
      AND     T181
      MOV     K2 D102
37    LD      M182
      OUT     T182 K10
      AND     T182
      MOV     K3 D102
45    LD      M183
      OUT     T183 K10
      AND     T183
      MOV     K4 D102
53    LD      M184
      OUT     T184 K10
      AND     T184
      MOV     K5 D102
61    LD      M185
      OUT     T185 K10
      AND     T185
      MOV     K6 D102
69    LD      M186
      OUT     T186 K10
      AND     T186
      MOV     K7 D102
77    LD      M187
      OUT     T187 K10
      AND     T187
      MOV     K8 D102
85    LD      M188
      OUT     T188 K10
      AND     T188
      MOV     K9 D102
93    LD      M189
      OUT     T189 K10
      AND     T189
      MOV     K10 D102
101   LD      M190
      OUT     T190 K10
      AND     T190
      MOV     K11 D102
109   LD      M191
      OUT     T191 K10
      AND     T191
      MOV     K12 D102
117   LD      M192
      OUT     T192 K10
      AND     T192
      MOV     K13 D102
125   LD      M193
      OUT     T193 K10
      AND     T193
      MOV     K14 D102
133   LD      M194
      OUT     T194 K10
      AND     T194
      MOV     K15 D102
141   LD      M195
      OUT     T195 K10
      AND     T195
      MOV     K16 D102
149   LD      M196
      OUT     T196 K10
      AND     T196
      MOV     K17 D102
157   LD      M197
      OUT     T197 K10
      AND     T197
      MOV     K18 D102
165   LD      M198
      OUT     T198 K10
      AND     T198
      MOV     K19 D102
173   LD      M199
      OUT     T199 K10
      AND     T199
      MOV     K20 D102
181   LD      M200
      OUT     T200 K10
      AND     T200
      MOV     K21 D102
189   LD      M201
      OUT     T201 K10
      AND     T201
      MOV     K22 D102
197   LD      M202
      OUT     T202 K10
      AND     T202
      MOV     K23 D102
205   LD      M203
      OUT     T203 K10
      AND     T203
      MOV     K24 D102
213   LD      M204
      OUT     T204 K10
      AND     T204
      MOV     K25 D102
221   LD      M205
      OUT     T205 K10
      AND     T205
      MOV     K26 D102
229   LD      M206
      OUT     T206 K10
      AND     T206
      MOV     K27 D102
237   LD      M207
      OUT     T207 K10
      AND     T207
      MOV     K28 D102
245   LD      M208
      OUT     T208 K10
      AND     T208
      MOV     K29 D102
253   LD      M209
      OUT     T209 K10
      AND     T209
      MOV     K30 D102
261   LD      M210
      OUT     T210 K10
      AND     T210
      MOV     K31 D102
269   LD      M211
      OUT     T211 K10
      AND     T211
      MOV     K0 D102
277   END
END_PROGRAM

PROGRAM AUTO_4
0     LD      SM400
      DECO    D103 M220 K5
; [Title]Start Step
16    LD      M220
      ANI     SM401  ; -
      MOV     K1 D103
; [Title]Step 1
29    LD      M221
      OUT     T221 K10
      AND     T221
      MOV     K2 D103
37    LD      M222
      OUT     T222 K10
      AND     T222
      MOV     K3 D103
45    LD      M223
      OUT     T223 K10
      AND     T223
      MOV     K4 D103
53    LD      M224
      OUT     T224 K10
      AND     T224
      MOV     K5 D103
61    LD      M225
      OUT     T225 K10
      AND     T225
      MOV     K6 D103
69    LD      M226
      OUT     T226 K10
      AND     T226
      MOV     K7 D103
77    LD      M227
      OUT     T227 K10
      AND     T227
      MOV     K8 D103
85    LD      M228
      OUT     T228 K10
      AND     T228
      MOV     K9 D103
93    LD      M229
      OUT     T229 K10
      AND     T229
      MOV     K10 D103
101   LD      M230
      OUT     T230 K10
      AND     T230
      MOV     K11 D103
109   LD      M231
      OUT     T231 K10
      AND     T231
      MOV     K12 D103
117   LD      M232
      OUT     T232 K10
      AND     T232
      MOV     K13 D103
125   LD      M233
      OUT     T233 K10
      AND     T233
      MOV     K14 D103
133   LD      M234
      OUT     T234 K10
      AND     T234
      MOV     K15 D103
141   LD      M235
      OUT     T235 K10
      AND     T235
      MOV     K16 D103
149   LD      M236
      OUT     T236 K10
      AND     T236
      MOV     K17 D103
157   LD      M237
      OUT     T237 K10
      AND     T237
      MOV     K18 D103
165   LD      M238
      OUT     T238 K10
      AND     T238
      MOV     K19 D103
173   LD      M239
      OUT     T239 K10
      AND     T239
      MOV     K20 D103
181   LD      M240
      OUT     T240 K10
      AND     T240
      MOV     K21 D103
189   LD      M241
      OUT     T241 K10
      AND     T241
      MOV     K22 D103
197   LD      M242
      OUT     T242 K10
      AND     T242
      MOV     K23 D103
205   LD      M243
      OUT     T243 K10
      AND     T243
      MOV     K24 D103
213   LD      M244
      OUT     T244 K10
      AND     T244
      MOV     K25 D103
221   LD      M245
      OUT     T245 K10
      AND     T245
      MOV     K26 D103
229   LD      M246
      OUT     T246 K10
      AND     T246
      MOV     K27 D103
237   LD      M247
      OUT     T247 K10
      AND     T247
      MOV     K28 D103
245   LD      M248
      OUT     T248 K10
      AND     T248
      MOV     K29 D103
253   LD      M249
      OUT     T249 K10
      AND     T249
      MOV     K30 D103
261   LD      M250
      OUT     T250 K10
      AND     T250
      MOV     K31 D103
269   LD      M251
      OUT     T251 K10
      AND     T251
      MOV     K0 D103
277   END
END_PROGRAM

PROGRAM AUTO_5
0     LD      SM400
      AND     M401  ; Auto Start Condition Transfer
      DECO    D104 M260 K5  ; Transfer Unit
6     LDI     X7  ; Emergency
      MOV     K0 D104
; [Title]AUTO FORCE DIRECTION
25    LD      L101  ; TRANSFER L SIDE
      MOV     K1 D10  ; AUTO MEMORY DIRECTION
      MEP
      RST     L102  ; TRANSFER R SIDE
30    LD      M410  ; FIRST STEP L SIDE
      MOVP    K1 D10
34    LD      L102  ; TRANSFER R SIDE
      MOV     K2 D10
      MEP
      RST     L101  ; TRANSFER L SIDE
39    LD      M411  ; FIRST STEP R SIDE
      MOVP    K2 D10
; [Title]Start Step
54    LD      M260
      AND     M401  ; Auto Start Condition Transfer
      LD      X5C9  ; Model A-1 Inprocess
      OR      X5CA  ; Model A-2 Inprocess
      OR      X5CB  ; Model B-1 Inprocess
      OR      X5CC  ; Model B-2 Inprocess
      OR      X5CD  ; Model C-1 Inprocess
      OR      X5CE  ; Model C-2 Inprocess
      ANB
      AND     SM400
      MOV     K13 D104
; [Title]Step 1 Motor RWD
80    LD      M261  ; ;Step 1 Motor RWD
      MPS
      AND     X580  ; LS RWD  Stop
      OUT     T261 K0
      MPP
      AND     T261
      MOV     K2 D104
; [Title]Step 2 Wait Robot Drop Complete
112   LD      M262  ; ;Step 2 Wait Robot Drop Complete
      MPS
      LD      X5E9  ; RB.Drop Complete
      AND     SM401  ; -
      LDI     X5EB  ; Drop Zone
      LD      X5E9  ; RB.Drop Complete
      OR      SM400
      ANB
      AND     B10  ; A:St.2 Possible START To PLC1
      AND     B11  ; A:St.2 Possible Conplete To PLC1
      ORB
      ANB
      AND     X587  ; PH.Check Work
      OUT     T262 K0
      MPP
      AND     T262
      MOV     K3 D104
; [Title]Step 3 Motor FWD  HI Speed
152   LD      M263  ; ;Step 3 Motor FWD  HI Speed
      MPS
      AND     X582  ; LS FWD  Slow    Speed
      OUT     T263 K0
      MPP
      AND     T263
      MOV     K4 D104
; [Title]Step 4 Motor FWD Low Speed
182   LD      M264  ; ;Step 4 Motor FWD Low Speed
      MPS
      AND     X583  ; LS FWD  Stop
      OUT     T264 K0
      MPP
      AND     T264
      MOV     K5 D104
; [Title]Step 5
202   LD      M265
      OUT     T265 K0
      AND     T265
      MOV     K6 D104
; [Title]Steop 6
219   LD      M266
      OUT     T266 K0
      AND     T266
      MOV     K7 D104
; [Title]Step 7
236   LD      M267
      MPS
      LD      X585  ; Px.Stop CCW
      OR      X586  ; Px.Stop CW
      ANB
      OUT     T267 K10
      MPP
      AND     T267
      MOV     K8 D104
; [Title]Step 8 Wait Pick complete
267   LD      M268  ; ;Step 8 Wait Pick complete
      MPS
      ANI     X587  ; PH.Check Work
      AND     X0  ; Light Curtain (1)Left
      AND     X1  ; Light Curtain (2) Right
      AND     M401  ; Auto Start Condition Transfer
      OUT     T268 K30
      MPP
      AND     T268
      MOV     K9 D104
; [Title]Step 9
290   LD      M269
      OUT     T269 K0
      AND     T269
      MOV     K10 D104
; [Title]Step 10 Motor RWD HI Speed
317   LD      M270  ; ;Step 10 Motor RWD HI Speed
      MPS
      LD      X581  ; LS RWD  Slow
      OR      X58F  ; LS STOP CENTER
      ANB
      OUT     T270 K0
      MPP
      AND     T270
      MOV     K11 D104
; [Title]Step 11 Motor RWD Low Speed
350   LD      M271  ; ;Step 11 Motor RWD Low Speed
      MPS
      LD      X580  ; LS RWD  Stop
      OR      X58F  ; LS STOP CENTER
      ANB
      OUT     T271 K0
      MPP
      AND     T271
      MOV     K12 D104
; [Title]Step 12 Turn Center
378   LD      M272
      MPS
      LD      X58A  ; PX.TRUN CENTER
      OR      SM400
      ANB
      OUT     T272 K0
      MRD
      AND     T272
      MOV     K0 D104
      MPP
      AND=    D10 K2  ; AUTO MEMORY DIRECTION
      MOV     K0 D10
; [Title]Step 13
406   LD      M273
      OUT     T273 K0
      AND     T273
      MOV     K14 D104
; [Title]Step 14
423   LD      M274  ; Motor Rwd Hi
      MPS
      LD      X581  ; LS RWD  Slow
      OR      X580  ; LS RWD  Stop
      ANB
      OUT     T274 K0
      MPP
      AND     T274
      MOV     K1 D104
436   LD      M275
      OUT     T275 K10
      AND     T275
      MOV     K16 D104
444   LD      M276
      OUT     T276 K10
      AND     T276
      MOV     K17 D104
452   LD      M277
      OUT     T277 K10
      AND     T277
      MOV     K18 D104
460   LD      M278
      OUT     T278 K10
      AND     T278
      MOV     K19 D104
468   LD      M279
      OUT     T279 K10
      AND     T279
      MOV     K20 D104
476   LD      M280
      OUT     T280 K10
      AND     T280
      MOV     K21 D104
484   LD      M281
      OUT     T281 K10
      AND     T281
      MOV     K22 D104
492   LD      M282
      OUT     T282 K10
      AND     T282
      MOV     K23 D104
500   LD      M283
      OUT     T283 K10
      AND     T283
      MOV     K24 D104
508   LD      M284
      OUT     T284 K10
      AND     T284
      MOV     K25 D104
516   LD      M285
      OUT     T285 K10
      AND     T285
      MOV     K26 D104
524   LD      M286
      OUT     T286 K10
      AND     T286
      MOV     K27 D104
532   LD      M287
      OUT     T287 K10
      AND     T287
      MOV     K28 D104
540   LD      M288
      OUT     T288 K10
      AND     T288
      MOV     K29 D104
548   LD      M289
      OUT     T289 K10
      AND     T289
      MOV     K30 D104
556   LD      M290
      OUT     T290 K10
      AND     T290
      MOV     K31 D104
564   LD      M291
      OUT     T291 K10
      AND     T291
      MOV     K0 D104
572   LD      M401  ; Auto Start Condition Transfer
      MOVP    K1 D10
576   LD      X58A  ; PX.TRUN CENTER
      INCP    D20  ; CNT PX  Center
580   LD      SM401  ; -
      AND     T11
      ORP     M40  ; Turn CW
      ORP     M41  ; Turn CCW
      ORP     M42  ; ;Return CW
      ORP     M43  ; ;Return CCW
      MOV     K0 D20
; [Title]Turn CW
601   LD      M30
      ORP     M263  ; ;Step 3 Motor FWD  HI Speed
      ANI     X586  ; Px.Stop CW
      AND=    D10 K1  ; AUTO MEMORY DIRECTION
      SET     M40  ; Turn CW
609   LD      X586  ; Px.Stop CW
      RST     M40  ; Turn CW
611   LDP     M261  ; ;Step 1 Motor RWD
      +P      K1 D10
; [Title]Turm CCW
627   LD      M31
      ORP     M263  ; ;Step 3 Motor FWD  HI Speed
      ANI     X585  ; Px.Stop CCW
      AND=    D10 K2  ; AUTO MEMORY DIRECTION
      SET     M41  ; Turn CCW
635   LD      X585  ; Px.Stop CCW
      RST     M41  ; Turn CCW
; [Title]Return CW
647   LD      M33
      LD      W607.8
      AND     X648  ; PB.RESTART
      ORB
      ORP     M270  ; ;Step 10 Motor RWD HI Speed
      ANI     X58A  ; PX.TRUN CENTER
      LD      X585  ; Px.Stop CCW
      LD      W607.8
      AND=    D45 K2  ; MEMORY DIRECTION TURNTABLE
      ORB
      ANB
      SET     M42  ; ;Return CW
      RST     M43  ; ;Return CCW
663   LD=     D20 K2  ; CNT PX  Center
      MPS
      AND     T11
      RST     M42  ; ;Return CW
      MPP
      OUT     T11 K1
; [Title]Return CCW
685   LD      M33
      LD      W607.8
      AND     X648  ; PB.RESTART
      ORB
      ORP     M270  ; ;Step 10 Motor RWD HI Speed
      ANI     X58A  ; PX.TRUN CENTER
      LD      X586  ; Px.Stop CW
      LD      W607.8
      AND=    D45 K1  ; MEMORY DIRECTION TURNTABLE
      ORB
      ANB
      SET     M43  ; ;Return CCW
      RST     M42  ; ;Return CW
701   LD      T11
      RST     M43  ; ;Return CCW
703   LDF     M42  ; ;Return CW
      ORP     M400  ; Auto Start Condition
      ORF     M43  ; ;Return CCW
      AND     X58A  ; PX.TRUN CENTER
      ORP     X585  ; Px.Stop CCW
      ORP     X586  ; Px.Stop CW
      SET     M44  ; Lock    Turn
715   LDP     M40  ; Turn CW
      ORP     M41  ; Turn CCW
      ORP     M90  ; Inv.2 CW
      ORP     M91  ; Inv.2 CcW
      LD      X642  ; SS.ADV
      OR      X643  ; SS.RET
      MEP
      AND     W607.8
      ORB
      RST     M44  ; Lock    Turn
729   LDI     X7  ; Emergency
      RST     M40  ; Turn CW
      RST     M41  ; Turn CCW
      RST     M42  ; ;Return CW
      RST     M43  ; ;Return CCW
734   END
END_PROGRAM

PROGRAM POE
; [Title]Fixed lenght mode setting-192.168.3.10
25    LDP     SM402
      MOV     K0 D402
      MOV     K10 D403
      SP.SOCRMODE "U0" K2 D400
; [Title]Connection No.1 Open Processing (Active)
69    LDP     SM412
      ANI     SD1282.1
      ANI     SD1284.1
      AND     SD1288.A
      MOVP    H0 D1000
      SP.SOCOPEN "U0" K2 D1000 M1000
90    LD      M400  ; Auto Start Condition
      AND=    D35 K5  ; CNT WORK MODEL C-2
      OR      M580
      OUT     M3000  ; 10-GROUP#1
96    LD      M400  ; Auto Start Condition
      AND=    D35 K4  ; CNT WORK MODEL C-2
      OR      M581
      OUT     M3001  ; 10-GROUP#2
102   LD      M400  ; Auto Start Condition
      AND=    D35 K3  ; CNT WORK MODEL C-2
      OR      M582
      OUT     M3002  ; 10-GROUP#3
108   LD      M400  ; Auto Start Condition
      AND=    D35 K2  ; CNT WORK MODEL C-2
      OR      M583
      OUT     M3003  ; 10-GROUP#4
114   LD      M400  ; Auto Start Condition
      AND=    D35 K1  ; CNT WORK MODEL C-2
      OR      M584
      OUT     M3004  ; 10-GROUP#5
120   LDI     X7  ; Emergency
      AND     SM401  ; -
      MEP
      LDI     M55  ; C-2 PALLETE READY
      MEP
      ORB
      OUT     M3005  ; 10-GROUP#6
127   LDP     M811  ; C-2 LOAD-IN READY
      OUT     M3007  ; 10-GROUP#8
130   LDP     M55  ; C-2 PALLETE READY
      OUT     M3009  ; 10-GROUP#10
133   LD      M3000  ; 10-GROUP#1
      MOV     K1 D1104
136   LD      M3001  ; 10-GROUP#2
      MOV     K2 D1104
139   LD      M3002  ; 10-GROUP#3
      MOV     K3 D1104
142   LD      M3003  ; 10-GROUP#4
      MOV     K4 D1104
145   LD      M3004  ; 10-GROUP#5
      MOV     K5 D1104
148   LD      M3005  ; 10-GROUP#6
      MOV     K6 D1104
151   LD      M3006  ; 10-GROUP#7
      MOV     K7 D1104
154   LD      M3007  ; 10-GROUP#8
      MOV     K8 D1104
157   LD      M3008  ; 10-GROUP#9
      MOV     K9 D1104
160   LD      M3009  ; 10-GROUP#10
      MOV     K10 D1104
163   LD      M3010  ; 10-GROUP#11
      MOV     K11 D1104
166   LD      M3011  ; 10-GROUP#12
      MOV     K12 D1104
169   LD      M3012  ; 10-GROUP#13
      MOV     K13 D1104
172   LD      M3013  ; 10-GROUP#14
      MOV     K14 D1104
175   LD      M3014  ; 10-GROUP#15
      MOV     K15 D1104
; [Title]Data Sending
190   LDP     M3000  ; 10-GROUP#1
      ORP     M3001  ; 10-GROUP#2
      ORP     M3002  ; 10-GROUP#3
      ORP     M3003  ; 10-GROUP#4
      ORP     M3004  ; 10-GROUP#5
      ORP     M3005  ; 10-GROUP#6
      ORP     M3006  ; 10-GROUP#7
      ORP     M3007  ; 10-GROUP#8
      ORP     M3008  ; 10-GROUP#9
      ORP     M3009  ; 10-GROUP#10
      ORP     M3010  ; 10-GROUP#11
      ORP     M3011  ; 10-GROUP#12
      ORP     M3012  ; 10-GROUP#13
      ORP     M3013  ; 10-GROUP#14
      ORP     M3014  ; 10-GROUP#15
      AND     SD1282.1
      MOVP    K7 D1100
      MPS
      AND     SM400
      MOV     H4241 D1101
      MOV     H54 D1102
      MOV     H100 D1103
      MPP
      SP.SOCSND "U0" K2 D3000 D1100 M300
; [Title]Data Clear
257   LDP     M3016
      LD      X644  ; PB.RESET (OP)
      ANI     X7  ; Emergency
      AND=    D1104 K6
      ORB
      AND     SD1282.1
      MOVP    K6 D1100
      MPS
      AND     SM400
      MOV     H4241 D1101
      MOV     H43 D1102
      MOV     H0 D1103
      MPP
      SP.SOCSND "U0" K2 D3000 D1100 M300
; [Title]Data Receiving
304   LD      SD1282.1
      AND     SD1286.1
      SP.SOCRCV "U0" K2 D5000 D500 M500
; [Title]Connection No.1 Close Processing
341   LDF     SD1282.1
      AND     SD1284.1
      PLS     M4001
346   LD      M4001
      ORP     M3017
      SP.SOCCLOSE "U0" K2 D200 M200
; [Title]Fixed lenght mode setting-192.168.3.11
387   LDP     SM402
      MOV     K0 D412
      MOV     K10 D413
      SP.SOCRMODE "U0" K3 D410
; [Title]Open Socket
416   LDP     SM412
      ANI     SD1282.2
      ANI     SD1284.2
      AND     SD1288.A
      MOVP    H0 D1001
      SP.SOCOPEN "U0" K3 D1001 M1001
437   LD      M400  ; Auto Start Condition
      AND=    D34 K5  ; CNT WORK MODEL C-1
      OUT     M3020  ; 11-GROUP#1
442   LD      M400  ; Auto Start Condition
      AND=    D34 K4  ; CNT WORK MODEL C-1
      OUT     M3021  ; 11-GROUP#2
447   LD      M400  ; Auto Start Condition
      AND=    D34 K3  ; CNT WORK MODEL C-1
      OUT     M3022  ; 11-GROUP#3
452   LD      M400  ; Auto Start Condition
      AND=    D34 K2  ; CNT WORK MODEL C-1
      OUT     M3023  ; 11-GROUP#4
457   LD      M400  ; Auto Start Condition
      AND=    D34 K1  ; CNT WORK MODEL C-1
      OUT     M3024  ; 11-GROUP#5
462   LDI     X7  ; Emergency
      AND     SM401  ; -
      MEP
      LDI     M54  ; C-1 PALLETE READY
      MEP
      ORB
      OUT     M3025  ; 11-GROUP#6
469   LDP     M809  ; C-1 LOAD-IN READY
      OUT     M3027  ; 11-GROUP#8
472   LDP     M54  ; C-1 PALLETE READY
      OUT     M3029  ; 11-GROUP#10
475   LD      M3020  ; 11-GROUP#1
      MOV     K1 D1204
478   LD      M3021  ; 11-GROUP#2
      MOV     K2 D1204
481   LD      M3022  ; 11-GROUP#3
      MOV     K3 D1204
484   LD      M3023  ; 11-GROUP#4
      MOV     K4 D1204
487   LD      M3024  ; 11-GROUP#5
      MOV     K5 D1204
490   LD      M3025  ; 11-GROUP#6
      MOV     K6 D1204
493   LD      M3026  ; 11-GROUP#7
      MOV     K7 D1204
496   LD      M3027  ; 11-GROUP#8
      MOV     K8 D1204
499   LD      M3028  ; 11-GROUP#9
      MOV     K9 D1204
502   LD      M3029  ; 11-GROUP#10
      MOV     K10 D1204
505   LD      M3030  ; 11-GROUP#11
      MOV     K11 D1204
508   LD      M3031  ; 11-GROUP#12
      MOV     K12 D1204
511   LD      M3032  ; 11-GROUP#13
      MOV     K13 D1204
514   LD      M3033  ; 11-GROUP#14
      MOV     K14 D1204
517   LD      M3034  ; 11-GROUP#15
      MOV     K15 D1204
; [Title]Data Sending 2
533   LDP     M3020  ; 11-GROUP#1
      ORP     M3021  ; 11-GROUP#2
      ORP     M3022  ; 11-GROUP#3
      ORP     M3023  ; 11-GROUP#4
      ORP     M3024  ; 11-GROUP#5
      ORP     M3025  ; 11-GROUP#6
      ORP     M3026  ; 11-GROUP#7
      ORP     M3027  ; 11-GROUP#8
      ORP     M3028  ; 11-GROUP#9
      ORP     M3029  ; 11-GROUP#10
      ORP     M3030  ; 11-GROUP#11
      ORP     M3031  ; 11-GROUP#12
      ORP     M3032  ; 11-GROUP#13
      ORP     M3033  ; 11-GROUP#14
      ORP     M3034  ; 11-GROUP#15
      AND     SD1282.2
      MOVP    K7 D1200
      MPS
      AND     SM400
      MOV     H4241 D1201
      MOV     H54 D1202
      MOV     H100 D1203
      MPP
      SP.SOCSND "U0" K3 D3000 D1200 M301
; [Title]Data Clear3
600   LDP     M3036
      LD      X644  ; PB.RESET (OP)
      ANI     X7  ; Emergency
      AND=    D1204 K6
      ORB
      AND     SD1282.2
      MOVP    K6 D1200
      MPS
      AND     SM400
      MOV     H4241 D1201
      MOV     H43 D1202
      MOV     H0 D1203
      MPP
      SP.SOCSND "U0" K3 D3000 D1200 M301
634   LD      SD1282.2
      AND     SD1286.2
      SP.SOCRCV "U0" K3 D5000 D500 M500
649   LDF     SD1282.2
      AND     SD1284.2
      PLS     M4001
; [Title]Socket Close
666   LD      M4001
      ORP     M3037
      SP.SOCCLOSE "U0" K3 D201 M201
; [Title]Fixed lenght mode setting-192.168.3.12
707   LDP     SM402
      MOV     K0 D412
      MOV     K10 D413
      SP.SOCRMODE "U0" K3 D410
; [Title]Open Socket2
737   LDP     SM412
      ANI     SD1282.3
      ANI     SD1284.3
      AND     SD1288.A
      MOVP    H0 D1002
      SP.SOCOPEN "U0" K4 D1002 M1002
758   LD      M400  ; Auto Start Condition
      AND=    D33 K5  ; CNT WORK MODEL B-2
      OUT     M3040  ; 12-GROUP#1
763   LD      M400  ; Auto Start Condition
      AND=    D33 K4  ; CNT WORK MODEL B-2
      OUT     M3041  ; 12-GROUP#2
768   LD      M400  ; Auto Start Condition
      AND=    D33 K3  ; CNT WORK MODEL B-2
      OUT     M3042  ; 12-GROUP#3
773   LD      M400  ; Auto Start Condition
      AND=    D33 K2  ; CNT WORK MODEL B-2
      OUT     M3043  ; 12-GROUP#4
778   LD      M400  ; Auto Start Condition
      AND=    D33 K1  ; CNT WORK MODEL B-2
      OUT     M3044  ; 12-GROUP#5
783   LDI     X7  ; Emergency
      AND     SM401  ; -
      MEP
      LDI     M53  ; B-2 PALLETE READY
      MEP
      ORB
      OUT     M3045  ; 12-GROUP#6
790   LDP     M807  ; B-2 LOAD-IN READY
      OUT     M3047  ; 12-GROUP#8
793   LDP     M53  ; B-2 PALLETE READY
      OUT     M3049  ; 12-GROUP#10
796   LD      M3040  ; 12-GROUP#1
      MOV     K1 D1304
799   LD      M3041  ; 12-GROUP#2
      MOV     K2 D1304
802   LD      M3042  ; 12-GROUP#3
      MOV     K3 D1304
805   LD      M3043  ; 12-GROUP#4
      MOV     K4 D1304
808   LD      M3044  ; 12-GROUP#5
      MOV     K5 D1304
811   LD      M3045  ; 12-GROUP#6
      MOV     K6 D1304
814   LD      M3046  ; 12-GROUP#7
      MOV     K7 D1304
817   LD      M3047  ; 12-GROUP#8
      MOV     K8 D1304
820   LD      M3048  ; 12-GROUP#9
      MOV     K9 D1304
823   LD      M3049  ; 12-GROUP#10
      MOV     K10 D1304
826   LD      M3050  ; 12-GROUP#11
      MOV     K11 D1304
829   LD      M3051  ; 12-GROUP#12
      MOV     K12 D1304
832   LD      M3052  ; 12-GROUP#13
      MOV     K13 D1304
835   LD      M3053  ; 12-GROUP#14
      MOV     K14 D1304
838   LD      M3054  ; 12-GROUP#15
      MOV     K15 D1304
841   LDP     M3040  ; 12-GROUP#1
      ORP     M3041  ; 12-GROUP#2
      ORP     M3042  ; 12-GROUP#3
      ORP     M3043  ; 12-GROUP#4
      ORP     M3044  ; 12-GROUP#5
      ORP     M3045  ; 12-GROUP#6
      ORP     M3046  ; 12-GROUP#7
      ORP     M3047  ; 12-GROUP#8
      ORP     M3048  ; 12-GROUP#9
      ORP     M3049  ; 12-GROUP#10
      ORP     M3050  ; 12-GROUP#11
      ORP     M3051  ; 12-GROUP#12
      ORP     M3052  ; 12-GROUP#13
      ORP     M3053  ; 12-GROUP#14
      ORP     M3054  ; 12-GROUP#15
      AND     SD1282.3
      MOVP    K7 D1300
      MPS
      AND     SM400
      MOV     H4241 D1301
      MOV     H54 D1302
      MOV     H100 D1303
      MPP
      SP.SOCSND "U0" K4 D3000 D1300 M302
; [Title]Data Clear4
908   LDP     M3056
      LD      X644  ; PB.RESET (OP)
      ANI     X7  ; Emergency
      AND=    D1304 K6
      ORB
      AND     SD1282.3
      MOVP    K6 D1300
      MPS
      AND     SM400
      MOV     H4241 D1301
      MOV     H43 D1302
      MOV     H0 D1303
      MPP
      SP.SOCSND "U0" K4 D3000 D1300 M301
942   LD      SD1282.3
      AND     SD1286.3
      SP.SOCRCV "U0" K4 D5000 D500 M500
957   LDF     SD1282.3
      AND     SD1284.3
      PLS     M4001
962   LD      M4001
      ORP     M3057
      SP.SOCCLOSE "U0" K4 D201 M201
; [Title]Fixed lenght mode setting-192.168.3.13
1003  LDP     SM402
      MOV     K0 D412
      MOV     K10 D413
      SP.SOCRMODE "U0" K5 D410
; [Title]Open Socket3
1033  LDP     SM412
      ANI     SD1282.4
      ANI     SD1284.4
      AND     SD1288.A
      MOVP    H0 D1002
      SP.SOCOPEN "U0" K5 D1002 M1003
1054  LD      M400  ; Auto Start Condition
      AND=    D32 K5  ; CNT WORK MODEL B-1
      OUT     M3060  ; 13-GROUP#1
1059  LD      M400  ; Auto Start Condition
      AND=    D32 K4  ; CNT WORK MODEL B-1
      OUT     M3061  ; 13-GROUP#2
1064  LD      M400  ; Auto Start Condition
      AND=    D32 K3  ; CNT WORK MODEL B-1
      OUT     M3062  ; 13-GROUP#3
1069  LD      M400  ; Auto Start Condition
      AND=    D32 K2  ; CNT WORK MODEL B-1
      OUT     M3063  ; 13-GROUP#4
1074  LD      M400  ; Auto Start Condition
      AND=    D32 K1  ; CNT WORK MODEL B-1
      OUT     M3064  ; 13-GROUP#5
1079  LDI     X7  ; Emergency
      AND     SM401  ; -
      MEP
      LDI     M52  ; B-1 PALLETE READY
      MEP
      ORB
      OUT     M3065  ; 13-GROUP#6
1086  LDP     M805  ; B-1 LOAD-IN READY
      OUT     M3067  ; 13-GROUP#8
1089  LDP     M52  ; B-1 PALLETE READY
      OUT     M3069  ; 13-GROUP#10
1092  LD      M3060  ; 13-GROUP#1
      MOV     K1 D1404
1095  LD      M3061  ; 13-GROUP#2
      MOV     K2 D1404
1098  LD      M3062  ; 13-GROUP#3
      MOV     K3 D1404
1101  LD      M3063  ; 13-GROUP#4
      MOV     K4 D1404
1104  LD      M3064  ; 13-GROUP#5
      MOV     K5 D1404
1107  LD      M3065  ; 13-GROUP#6
      MOV     K6 D1404
1110  LD      M3066  ; 13-GROUP#7
      MOV     K7 D1404
1113  LD      M3067  ; 13-GROUP#8
      MOV     K8 D1404
1116  LD      M3068  ; 13-GROUP#9
      MOV     K9 D1404
1119  LD      M3069  ; 13-GROUP#10
      MOV     K10 D1404
1122  LD      M3070  ; 13-GROUP#11
      MOV     K11 D1404
1125  LD      M3071  ; 13-GROUP#12
      MOV     K12 D1404
1128  LD      M3072  ; 13-GROUP#13
      MOV     K13 D1404
1131  LD      M3073  ; 13-GROUP#14
      MOV     K14 D1404
1134  LD      M3074  ; 13-GROUP#15
      MOV     K15 D1404
1137  LDP     M3060  ; 13-GROUP#1
      ORP     M3061  ; 13-GROUP#2
      ORP     M3062  ; 13-GROUP#3
      ORP     M3063  ; 13-GROUP#4
      ORP     M3064  ; 13-GROUP#5
      ORP     M3065  ; 13-GROUP#6
      ORP     M3066  ; 13-GROUP#7
      ORP     M3067  ; 13-GROUP#8
      ORP     M3068  ; 13-GROUP#9
      ORP     M3069  ; 13-GROUP#10
      ORP     M3070  ; 13-GROUP#11
      ORP     M3071  ; 13-GROUP#12
      ORP     M3072  ; 13-GROUP#13
      ORP     M3073  ; 13-GROUP#14
      ORP     M3074  ; 13-GROUP#15
      AND     SD1282.4
      MOVP    K7 D1400
      MPS
      AND     SM400
      MOV     H4241 D1401
      MOV     H54 D1402
      MOV     H100 D1403
      MPP
      SP.SOCSND "U0" K5 D3000 D1400 M302
1193  LDP     M3076
      LD      X644  ; PB.RESET (OP)
      ANI     X7  ; Emergency
      AND=    D1404 K6
      ORB
      AND     SD1282.4
      MOVP    K6 D1400
      MPS
      AND     SM400
      MOV     H4241 D1401
      MOV     H43 D1402
      MOV     H0 D1403
      MPP
      SP.SOCSND "U0" K5 D3000 D1400 M301
1227  LD      SD1282.4
      AND     SD1286.4
      SP.SOCRCV "U0" K5 D5000 D500 M500
1242  LDF     SD1282.3
      AND     SD1284.3
      PLS     M4001
1247  LD      M4001
      ORP     M3077
      SP.SOCCLOSE "U0" K5 D201 M201
; [Title]Fixed lenght mode setting-192.168.3.14
1288  LDP     SM402
      MOV     K0 D412
      MOV     K10 D413
      SP.SOCRMODE "U0" K6 D410
1306  LDP     SM412
      ANI     SD1282.5
      ANI     SD1284.5
      AND     SD1288.A
      MOVP    H0 D1002
      SP.SOCOPEN "U0" K6 D1002 M1003
1327  LD      M400  ; Auto Start Condition
      AND=    D31 K5  ; CNT WORK MODEL A-2
      OUT     M3080  ; 14-GROUP#1
1332  LD      M400  ; Auto Start Condition
      AND=    D31 K4  ; CNT WORK MODEL A-2
      OUT     M3081  ; 14-GROUP#2
1337  LD      M400  ; Auto Start Condition
      AND=    D31 K3  ; CNT WORK MODEL A-2
      OUT     M3082  ; 14-GROUP#3
1342  LD      M400  ; Auto Start Condition
      AND=    D31 K2  ; CNT WORK MODEL A-2
      OUT     M3083  ; 14-GROUP#4
1347  LD      M400  ; Auto Start Condition
      AND=    D31 K1  ; CNT WORK MODEL A-2
      OUT     M3084  ; 14-GROUP#5
1352  LDI     X7  ; Emergency
      AND     SM401  ; -
      MEP
      LDI     M51  ; A-2 PALLETE READY
      MEP
      ORB
      OUT     M3085  ; 14-GROUP#6
1359  LDP     M803  ; A-2 LOAD-IN READY
      OUT     M3087  ; 14-GROUP#8
1362  LDP     M51  ; A-2 PALLETE READY
      OUT     M3089  ; 14-GROUP#10
1365  LD      M3080  ; 14-GROUP#1
      MOV     K1 D1504
1368  LD      M3081  ; 14-GROUP#2
      MOV     K2 D1504
1371  LD      M3082  ; 14-GROUP#3
      MOV     K3 D1504
1374  LD      M3083  ; 14-GROUP#4
      MOV     K4 D1504
1377  LD      M3084  ; 14-GROUP#5
      MOV     K5 D1504
1380  LD      M3085  ; 14-GROUP#6
      MOV     K6 D1504
1383  LD      M3086  ; 14-GROUP#7
      MOV     K7 D1504
1386  LD      M3087  ; 14-GROUP#8
      MOV     K8 D1504
1389  LD      M3088  ; 14-GROUP#9
      MOV     K9 D1504
1392  LD      M3089  ; 14-GROUP#10
      MOV     K10 D1504
1395  LD      M3090  ; 14-GROUP#11
      MOV     K11 D1504
1398  LD      M3091  ; 14-GROUP#12
      MOV     K12 D1504
1401  LD      M3092  ; 14-GROUP#13
      MOV     K13 D1504
1404  LD      M3093  ; 14-GROUP#14
      MOV     K14 D1504
1407  LD      M3094  ; 14-GROUP#15
      MOV     K15 D1504
1410  LDP     M3080  ; 14-GROUP#1
      ORP     M3081  ; 14-GROUP#2
      ORP     M3082  ; 14-GROUP#3
      ORP     M3083  ; 14-GROUP#4
      ORP     M3084  ; 14-GROUP#5
      ORP     M3085  ; 14-GROUP#6
      ORP     M3086  ; 14-GROUP#7
      ORP     M3087  ; 14-GROUP#8
      ORP     M3088  ; 14-GROUP#9
      ORP     M3089  ; 14-GROUP#10
      ORP     M3090  ; 14-GROUP#11
      ORP     M3091  ; 14-GROUP#12
      ORP     M3092  ; 14-GROUP#13
      ORP     M3093  ; 14-GROUP#14
      ORP     M3094  ; 14-GROUP#15
      AND     SD1282.5
      MOVP    K7 D1500
      MPS
      AND     SM400
      MOV     H4241 D1501
      MOV     H54 D1502
      MOV     H100 D1503
      MPP
      SP.SOCSND "U0" K6 D3000 D1500 M304
1466  LDP     M3096
      LD      X644  ; PB.RESET (OP)
      ANI     X7  ; Emergency
      AND=    D1504 K6
      ORB
      AND     SD1282.5
      MOVP    K6 D1500
      MPS
      AND     SM400
      MOV     H4241 D1501
      MOV     H43 D1502
      MOV     H0 D1503
      MPP
      SP.SOCSND "U0" K6 D3000 D1500 M301
1500  LD      SD1282.5
      AND     SD1286.5
      SP.SOCRCV "U0" K6 D5000 D500 M500
1515  LDF     SD1282.5
      AND     SD1284.5
      PLS     M4001
1520  LD      M4001
      ORP     M3097
      SP.SOCCLOSE "U0" K6 D201 M201
; [Title]Fixed lenght mode setting-192.168.3.15
1561  LDP     SM402
      MOV     K0 D412
      MOV     K10 D413
      SP.SOCRMODE "U0" K7 D410
1579  LDP     SM412
      ANI     SD1282.6
      ANI     SD1284.6
      AND     SD1288.A
      MOVP    H0 D1002
      SP.SOCOPEN "U0" K7 D1002 M1003
1600  LD      M400  ; Auto Start Condition
      AND=    D30 K5  ; CNT WORK MODEL A-1
      OUT     M3100  ; 15-GROUP#1
1605  LD      M400  ; Auto Start Condition
      AND=    D30 K4  ; CNT WORK MODEL A-1
      OUT     M3101  ; 15-GROUP#2
1610  LD      M400  ; Auto Start Condition
      AND=    D30 K3  ; CNT WORK MODEL A-1
      OUT     M3102  ; 15-GROUP#3
1615  LD      M400  ; Auto Start Condition
      AND=    D30 K2  ; CNT WORK MODEL A-1
      OUT     M3103  ; 15-GROUP#4
1620  LD      M400  ; Auto Start Condition
      AND=    D30 K1  ; CNT WORK MODEL A-1
      OUT     M3104  ; 15-GROUP#5
1625  LDI     X7  ; Emergency
      AND     SM401  ; -
      MEP
      LDI     M50  ; A-1 PALLETE READY
      MEP
      ORB
      OUT     M3105  ; 15-GROUP#6
1632  LDP     M801  ; A-1 LOAD-IN READY
      OUT     M3107  ; 15-GROUP#8
1635  LDP     M50  ; A-1 PALLETE READY
      OUT     M3109  ; 15-GROUP#10
1638  LD      M3100  ; 15-GROUP#1
      MOV     K1 D1604
1641  LD      M3101  ; 15-GROUP#2
      MOV     K2 D1604
1644  LD      M3102  ; 15-GROUP#3
      MOV     K3 D1604
1647  LD      M3103  ; 15-GROUP#4
      MOV     K4 D1604
1650  LD      M3104  ; 15-GROUP#5
      MOV     K5 D1604
1653  LD      M3105  ; 15-GROUP#6
      MOV     K6 D1604
1656  LD      M3106  ; 15-GROUP#7
      MOV     K7 D1604
1659  LD      M3107  ; 15-GROUP#8
      MOV     K8 D1604
1662  LD      M3108  ; 15-GROUP#9
      MOV     K9 D1604
1665  LD      M3109  ; 15-GROUP#10
      MOV     K10 D1604
1668  LD      M3110  ; 15-GROUP#11
      MOV     K11 D1604
1671  LD      M3111  ; 15-GROUP#12
      MOV     K12 D1604
1674  LD      M3112  ; 15-GROUP#13
      MOV     K13 D1604
1677  LD      M3113  ; 15-GROUP#14
      MOV     K14 D1604
1680  LD      M3114  ; 15-GROUP#15
      MOV     K15 D1604
1683  LDP     M3100  ; 15-GROUP#1
      ORP     M3101  ; 15-GROUP#2
      ORP     M3102  ; 15-GROUP#3
      ORP     M3103  ; 15-GROUP#4
      ORP     M3104  ; 15-GROUP#5
      ORP     M3105  ; 15-GROUP#6
      ORP     M3106  ; 15-GROUP#7
      ORP     M3107  ; 15-GROUP#8
      ORP     M3108  ; 15-GROUP#9
      ORP     M3109  ; 15-GROUP#10
      ORP     M3110  ; 15-GROUP#11
      ORP     M3111  ; 15-GROUP#12
      ORP     M3112  ; 15-GROUP#13
      ORP     M3113  ; 15-GROUP#14
      ORP     M3114  ; 15-GROUP#15
      AND     SD1282.6
      MOVP    K7 D1600
      MPS
      AND     SM400
      MOV     H4241 D1601
      MOV     H54 D1602
      MOV     H100 D1603
      MPP
      SP.SOCSND "U0" K7 D3000 D1600 M304
1739  LDP     M3116
      LD      X644  ; PB.RESET (OP)
      ANI     X7  ; Emergency
      AND=    D1604 K6
      ORB
      AND     SD1282.6
      MOVP    K6 D1600
      MPS
      AND     SM400
      MOV     H4241 D1601
      MOV     H43 D1602
      MOV     H0 D1603
      MPP
      SP.SOCSND "U0" K7 D3000 D1600 M301
1773  LD      SD1282.6
      AND     SD1286.6
      SP.SOCRCV "U0" K7 D5000 D500 M500
1788  LDF     SD1282.6
      AND     SD1284.6
      PLS     M4001
1793  LD      M4001
      ORP     M3117
      SP.SOCCLOSE "U0" K7 D201 M201
1809  END
END_PROGRAM

PROGRAM ROBOT
; [Title]Mode A
9     LD      L100  ; ROBOT   ENABLE
      AND     M400  ; Auto Start Condition
      AND     B0  ; A:St.1 Possible START To PLC1
      ANI     M800  ; A-1 REQUEST LOAD-IN
      ANI     M802  ; A-2 REQUEST LOAD-IN
      ANI     M804  ; B-1 REQUEST LOAD-IN
      ANI     M806  ; B-2 REQUEST LOAD-IN
      ANI     M808  ; C-1 REQUEST LOAD-IN
      ANI     M810  ; C-2 REQUEST LOAD-IN
      MPS
      LD=     W0 K7  ; (A)St.1 Model Code DATA To PLC1
      OR=     W0 K10  ; (A)St.1 Model Code DATA To PLC1
      ANB
      ANI     X5C9  ; Model A-1 Inprocess
      ANI     X5CA  ; Model A-2 Inprocess
      ANI     X5CB  ; Model B-1 Inprocess
      ANI     X5CC  ; Model B-2 Inprocess
      ANI     X5CD  ; Model C-1 Inprocess
      ANI     X5CE  ; Model C-2 Inprocess
      MPS
      AND     T20
      OUT     Y5C0  ; Select Model A-1
      MPP
      AND     M50  ; A-1 PALLETE READY
      OUT     T20 K5
      MPP
      LD=     W0 K6  ; (A)St.1 Model Code DATA To PLC1
      OR=     W0 K8  ; (A)St.1 Model Code DATA To PLC1
      ANB
      ANI     X5C9  ; Model A-1 Inprocess
      ANI     X5CA  ; Model A-2 Inprocess
      ANI     X5CB  ; Model B-1 Inprocess
      ANI     X5CC  ; Model B-2 Inprocess
      ANI     X5CD  ; Model C-1 Inprocess
      ANI     X5CE  ; Model C-2 Inprocess
      MPS
      AND     T21
      OUT     Y5C1  ; Select Model A-2
      MPP
      AND     M51  ; A-2 PALLETE READY
      OUT     T21 K5
; [Title]Model B
73    LD      L100  ; ROBOT   ENABLE
      AND     M400  ; Auto Start Condition
      AND     B0  ; A:St.1 Possible START To PLC1
      ANI     M800  ; A-1 REQUEST LOAD-IN
      ANI     M802  ; A-2 REQUEST LOAD-IN
      ANI     M804  ; B-1 REQUEST LOAD-IN
      ANI     M806  ; B-2 REQUEST LOAD-IN
      ANI     M808  ; C-1 REQUEST LOAD-IN
      ANI     M810  ; C-2 REQUEST LOAD-IN
      MPS
      AND=    W0 K9  ; (A)St.1 Model Code DATA To PLC1
      ANI     X5C9  ; Model A-1 Inprocess
      ANI     X5CA  ; Model A-2 Inprocess
      ANI     X5CB  ; Model B-1 Inprocess
      ANI     X5CC  ; Model B-2 Inprocess
      ANI     X5CD  ; Model C-1 Inprocess
      ANI     X5CE  ; Model C-2 Inprocess
      MPS
      AND     T22
      OUT     Y5C2  ; Select Model B-1
      MPP
      AND     M52  ; B-1 PALLETE READY
      OUT     T22 K5
      MPP
      AND=    W0 K5  ; (A)St.1 Model Code DATA To PLC1
      ANI     X5C9  ; Model A-1 Inprocess
      ANI     X5CA  ; Model A-2 Inprocess
      ANI     X5CB  ; Model B-1 Inprocess
      ANI     X5CC  ; Model B-2 Inprocess
      ANI     X5CD  ; Model C-1 Inprocess
      ANI     X5CE  ; Model C-2 Inprocess
      MPS
      AND     T23
      OUT     Y5C3  ; Select Model B-2
      MPP
      AND     M53  ; B-2 PALLETE READY
      OUT     T23 K5
; [Title]Model C
129   LD      L100  ; ROBOT   ENABLE
      AND     M400  ; Auto Start Condition
      AND     B0  ; A:St.1 Possible START To PLC1
      ANI     M800  ; A-1 REQUEST LOAD-IN
      ANI     M802  ; A-2 REQUEST LOAD-IN
      ANI     M804  ; B-1 REQUEST LOAD-IN
      ANI     M806  ; B-2 REQUEST LOAD-IN
      ANI     M808  ; C-1 REQUEST LOAD-IN
      ANI     M810  ; C-2 REQUEST LOAD-IN
      MPS
      AND=    W0 K2  ; (A)St.1 Model Code DATA To PLC1
      ANI     X5C9  ; Model A-1 Inprocess
      ANI     X5CA  ; Model A-2 Inprocess
      ANI     X5CB  ; Model B-1 Inprocess
      ANI     X5CC  ; Model B-2 Inprocess
      ANI     X5CD  ; Model C-1 Inprocess
      ANI     X5CE  ; Model C-2 Inprocess
      MPS
      AND     T24
      OUT     Y5C4  ; Select Model C-1
      MPP
      AND     M54  ; C-1 PALLETE READY
      OUT     T24 K5
      MPP
      LD=     W0 K1  ; (A)St.1 Model Code DATA To PLC1
      OR=     W0 K3  ; (A)St.1 Model Code DATA To PLC1
      OR=     W0 K4  ; (A)St.1 Model Code DATA To PLC1
      ANB
      ANI     X5C9  ; Model A-1 Inprocess
      ANI     X5CA  ; Model A-2 Inprocess
      ANI     X5CB  ; Model B-1 Inprocess
      ANI     X5CC  ; Model B-2 Inprocess
      ANI     X5CD  ; Model C-1 Inprocess
      ANI     X5CE  ; Model C-2 Inprocess
      MPS
      AND     T25
      OUT     Y5C5  ; Select Model C-2
      MPP
      AND     M55  ; C-2 PALLETE READY
      OUT     T25 K5
183   LD      X5E1  ; Test    Interupt
      AND     SM401  ; -
      LD      X0C  ; PH.DOG  #1
      ANI     X5CB  ; Model B-1 Inprocess
      ANI     X5CC  ; Model B-2 Inprocess
      ORB
      OR      X0D  ; PH.DOG  #2
      LD      X0E  ; PH.DOG  #3
      ANI     X5CB  ; Model B-1 Inprocess
      ANI     X5CC  ; Model B-2 Inprocess
      ORB
      LDI     X5C9  ; Model A-1 Inprocess
      ANI     X5CA  ; Model A-2 Inprocess
      AND     X0F  ; PH.DOG  #4
      ORB
      OUT     T10 K0
202   LD      M16
      OR      T10
      OUT     Y5C6  ; Interupt Model A
205   LD      M17
      OR      T10
      OUT     Y5C7  ; Interupt Model B
208   LD      M18
      OR      T10
      OUT     Y5C8  ; Interupt Model C
211   LD      SM401  ; -
      OUT     Y5C9
213   LD      SM401  ; -
      OUT     Y5CA
215   LD      SM401  ; -
      OUT     Y5CB
217   LD      SM401  ; -
      OUT     Y5CC
219   LD      SM401  ; -
      OUT     Y5CD
221   LD      SM401  ; -
      OUT     Y5CE
223   LD      SM401  ; -
      OUT     Y5CF
; [Title]Output
226   LD      SM401  ; -
      OUT     Y5D0
228   LD      SM401  ; -
      OUT     Y5D1
230   LD      SM401  ; -
      OUT     Y5D2
232   LD      SM401  ; -
      OUT     Y5D3
234   LD      SM401  ; -
      OUT     Y5D4
236   LD      SM401  ; -
      OUT     Y5D5
238   LD      SM401  ; -
      OUT     Y5D6
240   LD      SM401  ; -
      OUT     Y5D7
242   LD      T12
      ANI     X5C9  ; Model A-1 Inprocess
      ANI     X5CA  ; Model A-2 Inprocess
      ANI     X5CB  ; Model B-1 Inprocess
      ANI     X5CC  ; Model B-2 Inprocess
      ANI     X5CD  ; Model C-1 Inprocess
      ANI     X5CE  ; Model C-2 Inprocess
      AND     SM400
      OUT     Y5D8  ; Program Strobe
251   LD      SM401  ; -
      OUT     Y5D9
253   LD      SM401  ; -
      OUT     Y5DA
255   LD      SM401  ; -
      OUT     Y5DB
257   LD      SM401  ; -
      OUT     Y5DC
259   LD      X5DC  ; Motor Energized
      MPS
      AND     T12
      OUT     Y5DD  ; Ext.Unit Play Start
      MPP
      OUT     T12 K10
268   LD      X5D8  ; InTeachMode
      ANI     X2  ; SAFETY PLUG 1(OUT SIDE)
      ANI     X3  ; SAFETY PLUG 2(OUT SIDE)
      AND     X4  ; SAFETY PLUG 3(IN SIDE)
      OR      M20
      OR      M400  ; Auto Start Condition
      OUT     Y5DE  ; Ext.Unit Play Stop
275   LD      M400  ; Auto Start Condition
      OUT     Y5DF  ; Ext.Motor -ON
; [Title]Output 2
278   LD      M71  ; PL AUTO
      LD      M70  ; PL MANUAL
      ANI     M71  ; PL AUTO
      ORB
      ANI     M400  ; Auto Start Condition
      ANI     X5D8  ; InTeachMode
      LD      X5D8  ; InTeachMode
      LDI     X4  ; SAFETY PLUG 3(IN SIDE)
      OR      X2  ; SAFETY PLUG 1(OUT SIDE)
      OR      X3  ; SAFETY PLUG 2(OUT SIDE)
      ANB
      ANI     SM401  ; -
      ORB
      OUT     Y5E0  ; Ext.Motor -OFF
292   LD      X644  ; PB.RESET (OP)
      LD      X5D4  ; Error   Port
      OR      X5D6  ; ROBOT ALARM PORT ERROR
      OR      X5DF  ; Information port
      ANB
      OUT     Y5E1  ; Ext.Reset
298   LDI     L103  ; RB.HOLD CONFIRM
      OUT     Y5E2  ; Ext.Hold
      OUT     Y5E3  ; Ext.Hold Reset
301   LD      SM401  ; -
      OUT     Y5E4
303   LD      SM401  ; -
      OUT     Y5E5
305   LD      SM401  ; -
      OUT     Y5E6
307   LD      X10  ; MAGNET RUN
      MPS
      AND     T30
      OUT     Y5E7  ; Magnet-ON
      MPP
      OUT     T30 K10
316   LDI     X10  ; MAGNET RUN
      MPS
      AND     T31
      OUT     Y5E8  ; Magnet-Release
      MPP
      OUT     T31 K10
325   LD      M262  ; ;Step 2 Wait Robot Drop Complete
      AND     X58A  ; PX.TRUN CENTER
      ANI     X587  ; PH.Check Work
      MPS
      AND     T79
      OUT     Y5E9  ; Transfer Ready
      MPP
      OUT     T79 K10
336   LDI     X0C  ; PH.DOG  #1
      ANI     X0D  ; PH.DOG  #2
      ANI     X0E  ; PH.DOG  #3
      ANI     X0F  ; PH.DOG  #4
      OUT     Y5EA  ; PH.confirm PIck Work
341   LD      SM401  ; -
      OUT     Y5EB
343   LD      SM401  ; -
      OUT     Y5EC
345   LD      SM401  ; -
      OUT     Y5ED
347   LD      SM401  ; -
      OUT     Y5EE
349   LD      SM401  ; -
      OUT     Y5EF
; [Title]Output 3
352   LD      SM401  ; -
      OUT     Y5F0
354   LD      SM401  ; -
      OUT     Y5F1
356   LD      SM401  ; -
      OUT     Y5F2
358   LD      SM401  ; -
      OUT     Y5F3
360   LD      SM401  ; -
      OUT     Y5F4
362   LD      SM401  ; -
      OUT     Y5F5
364   LD      SM401  ; -
      OUT     Y5F6
366   LD      SM401  ; -
      OUT     Y5F7
368   LD      SM401  ; -
      OUT     Y5F8
370   LD      SM401  ; -
      OUT     Y5F9
372   LD      SM401  ; -
      OUT     Y5FA
374   LD      SM401  ; -
      OUT     Y5FB
376   LD      SM401  ; -
      OUT     Y5FC
378   LD      SM401  ; -
      OUT     Y5FD
380   LD      SM401  ; -
      OUT     Y5FE
382   LD      SM401  ; -
      OUT     Y5FF
384   END
END_PROGRAM

PROGRAM S_CUMMU
; [Title]Station 1
10    LD      SM400
      MPS
      LD      M60
      LD      M400  ; Auto Start Condition
      LD      X5C9  ; Model A-1 Inprocess
      OR      X5CA  ; Model A-2 Inprocess
      OR      X5CB  ; Model B-1 Inprocess
      OR      X5CC  ; Model B-2 Inprocess
      OR      X5CD  ; Model C-1 Inprocess
      OR      X5CE  ; Model C-2 Inprocess
      ANB
      ORB
      ANB
      OUT     B400  ; (A)St.1 Running From PLC1
      MRD
      LD      M61
      LD      M400  ; Auto Start Condition
      LD      X5C9  ; Model A-1 Inprocess
      OR      X5CA  ; Model A-2 Inprocess
      OR      X5CB  ; Model B-1 Inprocess
      OR      X5CC  ; Model B-2 Inprocess
      OR      X5CD  ; Model C-1 Inprocess
      OR      X5CE  ; Model C-2 Inprocess
      ANB
      ORB
      ANB
      OUT     B401  ; (A)St.1 2nd START From PLC1
      MRD
      LD      M62
      LD      M400  ; Auto Start Condition
      AND     X5E9  ; RB.Drop Complete
      AND     B1  ; A:St.1 Possible Conplete To PLC1
      ORB
      ANB
      OUT     B402  ; (A)St.1 Complete From PLC1
      MRD
      AND     M63
      MOV     K0 W100  ; (A)St.1 Product Code
      MPP
      AND     M64
      MOV     K0 W101  ; (A)St.1 Product Pattern
; [Title]Station 2
63    LD      SM400
      MPS
      LD      M65
      LD      M400  ; Auto Start Condition
      AND>    D104 K2  ; Transfer Unit
      ORB
      ANB
      OUT     B410  ; (A)St2. Running From PLC1
      MRD
      LD      M66
      LD      M400  ; Auto Start Condition
      AND>    D104 K2  ; Transfer Unit
      ORB
      ANB
      OUT     B411  ; (A)St2. 2nd START From PLC1
      MRD
      LD      M67
      LD      M400  ; Auto Start Condition
      AND     M270  ; ;Step 10 Motor RWD HI Speed
      AND     B11  ; A:St.2 Possible Conplete To PLC1
      ORB
      ANB
      OUT     B412  ; (A)St2. Complete From PLC1
      MRD
      AND     M68
      MOV     K0 W110  ; (A)St.2 Product Code
      MPP
      AND     M69
      MOV     K0 W111  ; (A)St.2 Product Pattern
98    END
END_PROGRAM

// device comments not shown above
X584  ; LS.Center Stop
B20  ; A:St.3 Possible START To PLC1
B21  ; A:St.3 Possible Conplete To PLC1
B10A  ; SHUTTER UP
B10B  ; SHUTTER DOWN
B20A  ; PL.SHUTTER UP
B20B  ; PL.SHUTTER DOWN
B20E  ; PL.TRANSFER ADV
B20F  ; PL.TRANSFER RET
B210  ; PL.TURN ADV
B211  ; PL.TURN RET
B302  ; SHUTTER C-1 UP
B303  ; SHUTTER C-1 DOWN
B304  ; SHUTTER B-2 UP
B305  ; SHUTTER B-2 DOWN
B306  ; SHUTTER B-1 UP
B307  ; SHUTTER B-1 DOWN
B308  ; SHUTTER A-2 UP
B309  ; SHUTTER A-2 DOWN
B30A  ; SHUTTER UP
B30B  ; SHUTTER DOWN
B30C  ; TURN LOCK
B30D  ; TURN UNLOCK
B310  ; TURN ADV
B311  ; TURN RET
B420  ; (A)St3. Running From PLC1
B421  ; (A)St3. 2nd START From PLC1
B422  ; (A)St3. Complete From PLC17
W1  ; (A)St.1 S/# To PLC1
W2  ; (A)St.1 Rack No. To PLC1
W3  ; (A)St.1 Position No. To PLC1
W4  ; (A)St.1 Date TO PLC1
W7  ; (A)St.1 Next Model Code To PLC1
W8  ; (A)St.2 Model Code DATA To PLC1
W9  ; (A)St.2 S/# To PLC1
W0A  ; (A)St.2 Rack No. To PLC1
W0B  ; (A)St.2 Position No. To PLC1
W0C  ; (A)St.2 Date TO PLC1
W0F  ; (A)St.2 Next Model Code To PLC1
W10  ; (A)St.3 Model Code DATA To PLC1
W11  ; (A)St.3 S/# To PLC1
W12  ; (A)St.3 Rack No. To PLC1
W13  ; (A)St.3 Position No. To PLC1
W14  ; (A)St.3 Date TO PLC1
W17  ; (A)St.3 Next Model Code To PLC1
